VERSION 5.7 ;
  NOWIREEXTENSIONATPIN ON ;
  DIVIDERCHAR "/" ;
  BUSBITCHARS "[]" ;
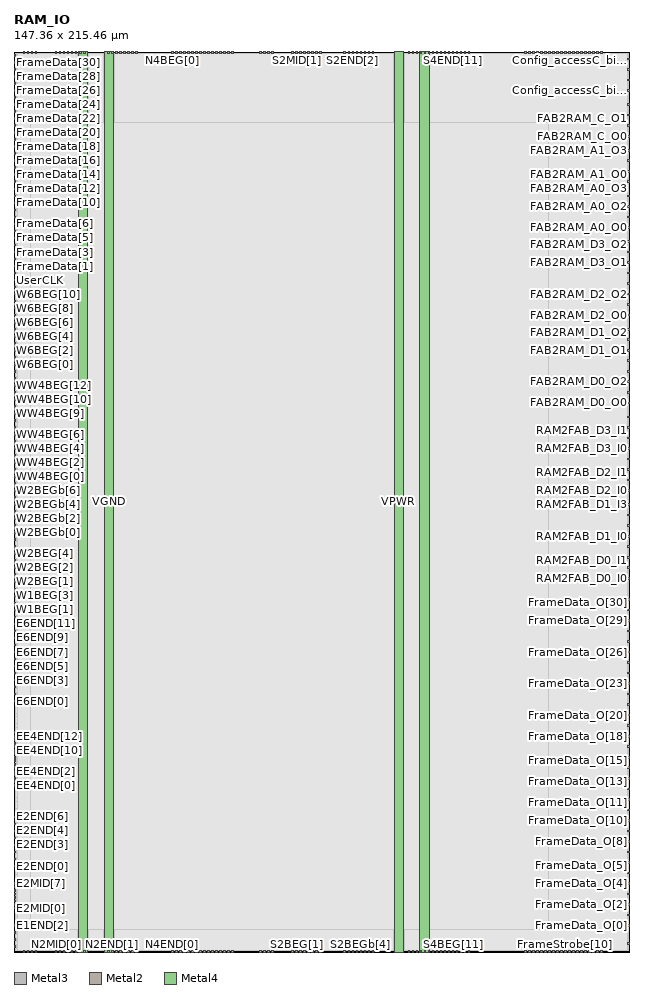
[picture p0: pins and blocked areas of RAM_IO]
MACRO RAM_IO
  CLASS BLOCK ;
  FOREIGN RAM_IO ;
  ORIGIN 0.000 0.000 ;
  SIZE 147.360 BY 215.460 ;
  PIN Config_accessC_bit0
    DIRECTION OUTPUT ;
    USE SIGNAL ;
    ANTENNADIFFAREA 2.647800 ;
    PORT
      LAYER Metal3 ;
        RECT 146.960 206.020 147.360 206.420 ;
    END
  END Config_accessC_bit0
  PIN Config_accessC_bit1
    DIRECTION OUTPUT ;
    USE SIGNAL ;
    ANTENNADIFFAREA 2.647800 ;
    PORT
      LAYER Metal3 ;
        RECT 146.960 208.540 147.360 208.940 ;
    END
  END Config_accessC_bit1
  PIN Config_accessC_bit2
    DIRECTION OUTPUT ;
    USE SIGNAL ;
    ANTENNADIFFAREA 2.647800 ;
    PORT
      LAYER Metal3 ;
        RECT 146.960 211.060 147.360 211.460 ;
    END
  END Config_accessC_bit2
  PIN Config_accessC_bit3
    DIRECTION OUTPUT ;
    USE SIGNAL ;
    ANTENNADIFFAREA 2.647800 ;
    PORT
      LAYER Metal3 ;
        RECT 146.960 213.580 147.360 213.980 ;
    END
  END Config_accessC_bit3
  PIN E1END[0]
    DIRECTION INPUT ;
    USE SIGNAL ;
    ANTENNAGATEAREA 1.521000 ;
    ANTENNADIFFAREA 14.107800 ;
    PORT
      LAYER Metal3 ;
        RECT 0.000 1.060 0.400 1.460 ;
    END
  END E1END[0]
  PIN E1END[1]
    DIRECTION INPUT ;
    USE SIGNAL ;
    ANTENNAGATEAREA 1.534000 ;
    ANTENNADIFFAREA 14.107800 ;
    PORT
      LAYER Metal3 ;
        RECT 0.000 2.740 0.400 3.140 ;
    END
  END E1END[1]
  PIN E1END[2]
    DIRECTION INPUT ;
    USE SIGNAL ;
    ANTENNAGATEAREA 1.521000 ;
    ANTENNADIFFAREA 14.107800 ;
    PORT
      LAYER Metal3 ;
        RECT 0.000 4.420 0.400 4.820 ;
    END
  END E1END[2]
  PIN E1END[3]
    DIRECTION INPUT ;
    USE SIGNAL ;
    ANTENNAGATEAREA 1.534000 ;
    ANTENNADIFFAREA 14.107800 ;
    PORT
      LAYER Metal3 ;
        RECT 0.000 6.100 0.400 6.500 ;
    END
  END E1END[3]
  PIN E2END[0]
    DIRECTION INPUT ;
    USE SIGNAL ;
    ANTENNAGATEAREA 0.668200 ;
    ANTENNADIFFAREA 6.046200 ;
    PORT
      LAYER Metal3 ;
        RECT 0.000 20.380 0.400 20.780 ;
    END
  END E2END[0]
  PIN E2END[1]
    DIRECTION INPUT ;
    USE SIGNAL ;
    ANTENNAGATEAREA 0.668200 ;
    ANTENNADIFFAREA 6.046200 ;
    PORT
      LAYER Metal3 ;
        RECT 0.000 22.060 0.400 22.460 ;
    END
  END E2END[1]
  PIN E2END[2]
    DIRECTION INPUT ;
    USE SIGNAL ;
    ANTENNAGATEAREA 0.668200 ;
    ANTENNADIFFAREA 6.046200 ;
    PORT
      LAYER Metal3 ;
        RECT 0.000 23.740 0.400 24.140 ;
    END
  END E2END[2]
  PIN E2END[3]
    DIRECTION INPUT ;
    USE SIGNAL ;
    ANTENNAGATEAREA 0.668200 ;
    ANTENNADIFFAREA 6.046200 ;
    PORT
      LAYER Metal3 ;
        RECT 0.000 25.420 0.400 25.820 ;
    END
  END E2END[3]
  PIN E2END[4]
    DIRECTION INPUT ;
    USE SIGNAL ;
    ANTENNAGATEAREA 0.668200 ;
    ANTENNADIFFAREA 6.046200 ;
    PORT
      LAYER Metal3 ;
        RECT 0.000 27.100 0.400 27.500 ;
    END
  END E2END[4]
  PIN E2END[5]
    DIRECTION INPUT ;
    USE SIGNAL ;
    ANTENNAGATEAREA 0.668200 ;
    ANTENNADIFFAREA 6.046200 ;
    PORT
      LAYER Metal3 ;
        RECT 0.000 28.780 0.400 29.180 ;
    END
  END E2END[5]
  PIN E2END[6]
    DIRECTION INPUT ;
    USE SIGNAL ;
    ANTENNAGATEAREA 0.668200 ;
    ANTENNADIFFAREA 6.046200 ;
    PORT
      LAYER Metal3 ;
        RECT 0.000 30.460 0.400 30.860 ;
    END
  END E2END[6]
  PIN E2END[7]
    DIRECTION INPUT ;
    USE SIGNAL ;
    ANTENNAGATEAREA 0.668200 ;
    ANTENNADIFFAREA 6.046200 ;
    PORT
      LAYER Metal3 ;
        RECT 0.000 32.140 0.400 32.540 ;
    END
  END E2END[7]
  PIN E2MID[0]
    DIRECTION INPUT ;
    USE SIGNAL ;
    ANTENNAGATEAREA 0.672100 ;
    ANTENNADIFFAREA 6.046200 ;
    PORT
      LAYER Metal3 ;
        RECT 0.000 10.300 0.400 10.700 ;
    END
  END E2MID[0]
  PIN E2MID[1]
    DIRECTION INPUT ;
    USE SIGNAL ;
    ANTENNAGATEAREA 0.672100 ;
    ANTENNADIFFAREA 6.046200 ;
    PORT
      LAYER Metal3 ;
        RECT 0.000 11.140 0.400 11.540 ;
    END
  END E2MID[1]
  PIN E2MID[2]
    DIRECTION INPUT ;
    USE SIGNAL ;
    ANTENNAGATEAREA 0.672100 ;
    ANTENNADIFFAREA 6.046200 ;
    PORT
      LAYER Metal3 ;
        RECT 0.000 11.980 0.400 12.380 ;
    END
  END E2MID[2]
  PIN E2MID[3]
    DIRECTION INPUT ;
    USE SIGNAL ;
    ANTENNAGATEAREA 0.672100 ;
    ANTENNADIFFAREA 6.046200 ;
    PORT
      LAYER Metal3 ;
        RECT 0.000 12.820 0.400 13.220 ;
    END
  END E2MID[3]
  PIN E2MID[4]
    DIRECTION INPUT ;
    USE SIGNAL ;
    ANTENNAGATEAREA 0.672100 ;
    ANTENNADIFFAREA 6.046200 ;
    PORT
      LAYER Metal3 ;
        RECT 0.000 13.660 0.400 14.060 ;
    END
  END E2MID[4]
  PIN E2MID[5]
    DIRECTION INPUT ;
    USE SIGNAL ;
    ANTENNAGATEAREA 0.672100 ;
    ANTENNADIFFAREA 6.046200 ;
    PORT
      LAYER Metal3 ;
        RECT 0.000 14.500 0.400 14.900 ;
    END
  END E2MID[5]
  PIN E2MID[6]
    DIRECTION INPUT ;
    USE SIGNAL ;
    ANTENNAGATEAREA 0.672100 ;
    ANTENNADIFFAREA 6.046200 ;
    PORT
      LAYER Metal3 ;
        RECT 0.000 15.340 0.400 15.740 ;
    END
  END E2MID[6]
  PIN E2MID[7]
    DIRECTION INPUT ;
    USE SIGNAL ;
    ANTENNAGATEAREA 0.672100 ;
    ANTENNADIFFAREA 6.046200 ;
    PORT
      LAYER Metal3 ;
        RECT 0.000 16.180 0.400 16.580 ;
    END
  END E2MID[7]
  PIN E6END[0]
    DIRECTION INPUT ;
    USE SIGNAL ;
    ANTENNAGATEAREA 0.668200 ;
    ANTENNADIFFAREA 6.046200 ;
    PORT
      LAYER Metal3 ;
        RECT 0.000 59.860 0.400 60.260 ;
    END
  END E6END[0]
  PIN E6END[10]
    DIRECTION INPUT ;
    USE SIGNAL ;
    ANTENNAGATEAREA 0.852800 ;
    ANTENNADIFFAREA 8.061600 ;
    PORT
      LAYER Metal3 ;
        RECT 0.000 76.660 0.400 77.060 ;
    END
  END E6END[10]
  PIN E6END[11]
    DIRECTION INPUT ;
    USE SIGNAL ;
    ANTENNAGATEAREA 0.865800 ;
    ANTENNADIFFAREA 8.061600 ;
    PORT
      LAYER Metal3 ;
        RECT 0.000 78.340 0.400 78.740 ;
    END
  END E6END[11]
  PIN E6END[1]
    DIRECTION INPUT ;
    USE SIGNAL ;
    ANTENNAGATEAREA 0.910000 ;
    ANTENNADIFFAREA 8.061600 ;
    PORT
      LAYER Metal3 ;
        RECT 0.000 61.540 0.400 61.940 ;
    END
  END E6END[1]
  PIN E6END[2]
    DIRECTION INPUT ;
    USE SIGNAL ;
    ANTENNAGATEAREA 0.668200 ;
    ANTENNADIFFAREA 6.046200 ;
    PORT
      LAYER Metal3 ;
        RECT 0.000 63.220 0.400 63.620 ;
    END
  END E6END[2]
  PIN E6END[3]
    DIRECTION INPUT ;
    USE SIGNAL ;
    ANTENNAGATEAREA 0.668200 ;
    ANTENNADIFFAREA 6.046200 ;
    PORT
      LAYER Metal3 ;
        RECT 0.000 64.900 0.400 65.300 ;
    END
  END E6END[3]
  PIN E6END[4]
    DIRECTION INPUT ;
    USE SIGNAL ;
    ANTENNAGATEAREA 0.852800 ;
    ANTENNADIFFAREA 8.061600 ;
    PORT
      LAYER Metal3 ;
        RECT 0.000 66.580 0.400 66.980 ;
    END
  END E6END[4]
  PIN E6END[5]
    DIRECTION INPUT ;
    USE SIGNAL ;
    ANTENNAGATEAREA 0.881400 ;
    ANTENNADIFFAREA 8.061600 ;
    PORT
      LAYER Metal3 ;
        RECT 0.000 68.260 0.400 68.660 ;
    END
  END E6END[5]
  PIN E6END[6]
    DIRECTION INPUT ;
    USE SIGNAL ;
    ANTENNAGATEAREA 0.852800 ;
    ANTENNADIFFAREA 8.061600 ;
    PORT
      LAYER Metal3 ;
        RECT 0.000 69.940 0.400 70.340 ;
    END
  END E6END[6]
  PIN E6END[7]
    DIRECTION INPUT ;
    USE SIGNAL ;
    ANTENNAGATEAREA 0.852800 ;
    ANTENNADIFFAREA 8.061600 ;
    PORT
      LAYER Metal3 ;
        RECT 0.000 71.620 0.400 72.020 ;
    END
  END E6END[7]
  PIN E6END[8]
    DIRECTION INPUT ;
    USE SIGNAL ;
    ANTENNAGATEAREA 0.865800 ;
    ANTENNADIFFAREA 8.061600 ;
    PORT
      LAYER Metal3 ;
        RECT 0.000 73.300 0.400 73.700 ;
    END
  END E6END[8]
  PIN E6END[9]
    DIRECTION INPUT ;
    USE SIGNAL ;
    ANTENNAGATEAREA 0.865800 ;
    ANTENNADIFFAREA 8.061600 ;
    PORT
      LAYER Metal3 ;
        RECT 0.000 74.980 0.400 75.380 ;
    END
  END E6END[9]
  PIN EE4END[0]
    DIRECTION INPUT ;
    USE SIGNAL ;
    ANTENNAGATEAREA 0.639600 ;
    ANTENNADIFFAREA 6.046200 ;
    PORT
      LAYER Metal3 ;
        RECT 0.000 39.700 0.400 40.100 ;
    END
  END EE4END[0]
  PIN EE4END[10]
    DIRECTION INPUT ;
    USE SIGNAL ;
    ANTENNAGATEAREA 0.426400 ;
    ANTENNADIFFAREA 4.030800 ;
    PORT
      LAYER Metal3 ;
        RECT 0.000 48.100 0.400 48.500 ;
    END
  END EE4END[10]
  PIN EE4END[11]
    DIRECTION INPUT ;
    USE SIGNAL ;
    ANTENNAGATEAREA 0.426400 ;
    ANTENNADIFFAREA 4.030800 ;
    PORT
      LAYER Metal3 ;
        RECT 0.000 48.940 0.400 49.340 ;
    END
  END EE4END[11]
  PIN EE4END[12]
    DIRECTION INPUT ;
    USE SIGNAL ;
    ANTENNAGATEAREA 0.639600 ;
    ANTENNADIFFAREA 6.046200 ;
    PORT
      LAYER Metal3 ;
        RECT 0.000 49.780 0.400 50.180 ;
    END
  END EE4END[12]
  PIN EE4END[13]
    DIRECTION INPUT ;
    USE SIGNAL ;
    ANTENNAGATEAREA 0.639600 ;
    ANTENNADIFFAREA 6.046200 ;
    PORT
      LAYER Metal3 ;
        RECT 0.000 50.620 0.400 51.020 ;
    END
  END EE4END[13]
  PIN EE4END[14]
    DIRECTION INPUT ;
    USE SIGNAL ;
    ANTENNAGATEAREA 0.639600 ;
    ANTENNADIFFAREA 6.046200 ;
    PORT
      LAYER Metal3 ;
        RECT 0.000 51.460 0.400 51.860 ;
    END
  END EE4END[14]
  PIN EE4END[15]
    DIRECTION INPUT ;
    USE SIGNAL ;
    ANTENNAGATEAREA 0.639600 ;
    ANTENNADIFFAREA 6.046200 ;
    PORT
      LAYER Metal3 ;
        RECT 0.000 52.300 0.400 52.700 ;
    END
  END EE4END[15]
  PIN EE4END[1]
    DIRECTION INPUT ;
    USE SIGNAL ;
    ANTENNAGATEAREA 0.705400 ;
    ANTENNADIFFAREA 6.046200 ;
    PORT
      LAYER Metal3 ;
        RECT 0.000 40.540 0.400 40.940 ;
    END
  END EE4END[1]
  PIN EE4END[2]
    DIRECTION INPUT ;
    USE SIGNAL ;
    ANTENNAGATEAREA 0.639600 ;
    ANTENNADIFFAREA 6.046200 ;
    PORT
      LAYER Metal3 ;
        RECT 0.000 41.380 0.400 41.780 ;
    END
  END EE4END[2]
  PIN EE4END[3]
    DIRECTION INPUT ;
    USE SIGNAL ;
    ANTENNAGATEAREA 0.705400 ;
    ANTENNADIFFAREA 6.046200 ;
    PORT
      LAYER Metal3 ;
        RECT 0.000 42.220 0.400 42.620 ;
    END
  END EE4END[3]
  PIN EE4END[4]
    DIRECTION INPUT ;
    USE SIGNAL ;
    ANTENNAGATEAREA 0.426400 ;
    ANTENNADIFFAREA 4.030800 ;
    PORT
      LAYER Metal3 ;
        RECT 0.000 43.060 0.400 43.460 ;
    END
  END EE4END[4]
  PIN EE4END[5]
    DIRECTION INPUT ;
    USE SIGNAL ;
    ANTENNAGATEAREA 0.426400 ;
    ANTENNADIFFAREA 4.030800 ;
    PORT
      LAYER Metal3 ;
        RECT 0.000 43.900 0.400 44.300 ;
    END
  END EE4END[5]
  PIN EE4END[6]
    DIRECTION INPUT ;
    USE SIGNAL ;
    ANTENNAGATEAREA 0.426400 ;
    ANTENNADIFFAREA 4.030800 ;
    PORT
      LAYER Metal3 ;
        RECT 0.000 44.740 0.400 45.140 ;
    END
  END EE4END[6]
  PIN EE4END[7]
    DIRECTION INPUT ;
    USE SIGNAL ;
    ANTENNAGATEAREA 0.426400 ;
    ANTENNADIFFAREA 4.030800 ;
    PORT
      LAYER Metal3 ;
        RECT 0.000 45.580 0.400 45.980 ;
    END
  END EE4END[7]
  PIN EE4END[8]
    DIRECTION INPUT ;
    USE SIGNAL ;
    ANTENNAGATEAREA 0.426400 ;
    ANTENNADIFFAREA 4.030800 ;
    PORT
      LAYER Metal3 ;
        RECT 0.000 46.420 0.400 46.820 ;
    END
  END EE4END[8]
  PIN EE4END[9]
    DIRECTION INPUT ;
    USE SIGNAL ;
    ANTENNAGATEAREA 0.426400 ;
    ANTENNADIFFAREA 4.030800 ;
    PORT
      LAYER Metal3 ;
        RECT 0.000 47.260 0.400 47.660 ;
    END
  END EE4END[9]
  PIN FAB2RAM_A0_O0
    DIRECTION OUTPUT ;
    USE SIGNAL ;
    ANTENNADIFFAREA 3.023500 ;
    PORT
      LAYER Metal3 ;
        RECT 146.960 173.260 147.360 173.660 ;
    END
  END FAB2RAM_A0_O0
  PIN FAB2RAM_A0_O1
    DIRECTION OUTPUT ;
    USE SIGNAL ;
    ANTENNADIFFAREA 3.023500 ;
    PORT
      LAYER Metal3 ;
        RECT 146.960 175.780 147.360 176.180 ;
    END
  END FAB2RAM_A0_O1
  PIN FAB2RAM_A0_O2
    DIRECTION OUTPUT ;
    USE SIGNAL ;
    ANTENNADIFFAREA 3.023500 ;
    PORT
      LAYER Metal3 ;
        RECT 146.960 178.300 147.360 178.700 ;
    END
  END FAB2RAM_A0_O2
  PIN FAB2RAM_A0_O3
    DIRECTION OUTPUT ;
    USE SIGNAL ;
    ANTENNADIFFAREA 3.023500 ;
    PORT
      LAYER Metal3 ;
        RECT 146.960 180.820 147.360 181.220 ;
    END
  END FAB2RAM_A0_O3
  PIN FAB2RAM_A1_O0
    DIRECTION OUTPUT ;
    USE SIGNAL ;
    ANTENNADIFFAREA 3.023500 ;
    PORT
      LAYER Metal3 ;
        RECT 146.960 184.180 147.360 184.580 ;
    END
  END FAB2RAM_A1_O0
  PIN FAB2RAM_A1_O1
    DIRECTION OUTPUT ;
    USE SIGNAL ;
    ANTENNADIFFAREA 3.023500 ;
    PORT
      LAYER Metal3 ;
        RECT 146.960 186.700 147.360 187.100 ;
    END
  END FAB2RAM_A1_O1
  PIN FAB2RAM_A1_O2
    DIRECTION OUTPUT ;
    USE SIGNAL ;
    ANTENNADIFFAREA 3.023500 ;
    PORT
      LAYER Metal3 ;
        RECT 146.960 189.220 147.360 189.620 ;
    END
  END FAB2RAM_A1_O2
  PIN FAB2RAM_A1_O3
    DIRECTION OUTPUT ;
    USE SIGNAL ;
    ANTENNADIFFAREA 3.023500 ;
    PORT
      LAYER Metal3 ;
        RECT 146.960 191.740 147.360 192.140 ;
    END
  END FAB2RAM_A1_O3
  PIN FAB2RAM_C_O0
    DIRECTION OUTPUT ;
    USE SIGNAL ;
    ANTENNADIFFAREA 2.692600 ;
    PORT
      LAYER Metal3 ;
        RECT 146.960 195.100 147.360 195.500 ;
    END
  END FAB2RAM_C_O0
  PIN FAB2RAM_C_O1
    DIRECTION OUTPUT ;
    USE SIGNAL ;
    ANTENNADIFFAREA 3.023500 ;
    PORT
      LAYER Metal3 ;
        RECT 146.960 197.620 147.360 198.020 ;
    END
  END FAB2RAM_C_O1
  PIN FAB2RAM_C_O2
    DIRECTION OUTPUT ;
    USE SIGNAL ;
    ANTENNADIFFAREA 2.692600 ;
    PORT
      LAYER Metal3 ;
        RECT 146.960 200.140 147.360 200.540 ;
    END
  END FAB2RAM_C_O2
  PIN FAB2RAM_C_O3
    DIRECTION OUTPUT ;
    USE SIGNAL ;
    ANTENNADIFFAREA 2.692600 ;
    PORT
      LAYER Metal3 ;
        RECT 146.960 202.660 147.360 203.060 ;
    END
  END FAB2RAM_C_O3
  PIN FAB2RAM_D0_O0
    DIRECTION OUTPUT ;
    USE SIGNAL ;
    ANTENNADIFFAREA 3.023500 ;
    PORT
      LAYER Metal3 ;
        RECT 146.960 131.260 147.360 131.660 ;
    END
  END FAB2RAM_D0_O0
  PIN FAB2RAM_D0_O1
    DIRECTION OUTPUT ;
    USE SIGNAL ;
    ANTENNADIFFAREA 3.023500 ;
    PORT
      LAYER Metal3 ;
        RECT 146.960 133.780 147.360 134.180 ;
    END
  END FAB2RAM_D0_O1
  PIN FAB2RAM_D0_O2
    DIRECTION OUTPUT ;
    USE SIGNAL ;
    ANTENNADIFFAREA 3.023500 ;
    PORT
      LAYER Metal3 ;
        RECT 146.960 136.300 147.360 136.700 ;
    END
  END FAB2RAM_D0_O2
  PIN FAB2RAM_D0_O3
    DIRECTION OUTPUT ;
    USE SIGNAL ;
    ANTENNADIFFAREA 3.023500 ;
    PORT
      LAYER Metal3 ;
        RECT 146.960 138.820 147.360 139.220 ;
    END
  END FAB2RAM_D0_O3
  PIN FAB2RAM_D1_O0
    DIRECTION OUTPUT ;
    USE SIGNAL ;
    ANTENNADIFFAREA 3.023500 ;
    PORT
      LAYER Metal3 ;
        RECT 146.960 141.340 147.360 141.740 ;
    END
  END FAB2RAM_D1_O0
  PIN FAB2RAM_D1_O1
    DIRECTION OUTPUT ;
    USE SIGNAL ;
    ANTENNADIFFAREA 3.023500 ;
    PORT
      LAYER Metal3 ;
        RECT 146.960 143.860 147.360 144.260 ;
    END
  END FAB2RAM_D1_O1
  PIN FAB2RAM_D1_O2
    DIRECTION OUTPUT ;
    USE SIGNAL ;
    ANTENNADIFFAREA 3.023500 ;
    PORT
      LAYER Metal3 ;
        RECT 146.960 146.380 147.360 146.780 ;
    END
  END FAB2RAM_D1_O2
  PIN FAB2RAM_D1_O3
    DIRECTION OUTPUT ;
    USE SIGNAL ;
    ANTENNADIFFAREA 3.023500 ;
    PORT
      LAYER Metal3 ;
        RECT 146.960 148.900 147.360 149.300 ;
    END
  END FAB2RAM_D1_O3
  PIN FAB2RAM_D2_O0
    DIRECTION OUTPUT ;
    USE SIGNAL ;
    ANTENNADIFFAREA 3.023500 ;
    PORT
      LAYER Metal3 ;
        RECT 146.960 152.260 147.360 152.660 ;
    END
  END FAB2RAM_D2_O0
  PIN FAB2RAM_D2_O1
    DIRECTION OUTPUT ;
    USE SIGNAL ;
    ANTENNADIFFAREA 3.023500 ;
    PORT
      LAYER Metal3 ;
        RECT 146.960 154.780 147.360 155.180 ;
    END
  END FAB2RAM_D2_O1
  PIN FAB2RAM_D2_O2
    DIRECTION OUTPUT ;
    USE SIGNAL ;
    ANTENNADIFFAREA 3.023500 ;
    PORT
      LAYER Metal3 ;
        RECT 146.960 157.300 147.360 157.700 ;
    END
  END FAB2RAM_D2_O2
  PIN FAB2RAM_D2_O3
    DIRECTION OUTPUT ;
    USE SIGNAL ;
    ANTENNADIFFAREA 3.023500 ;
    PORT
      LAYER Metal3 ;
        RECT 146.960 159.820 147.360 160.220 ;
    END
  END FAB2RAM_D2_O3
  PIN FAB2RAM_D3_O0
    DIRECTION OUTPUT ;
    USE SIGNAL ;
    ANTENNADIFFAREA 3.023500 ;
    PORT
      LAYER Metal3 ;
        RECT 146.960 162.340 147.360 162.740 ;
    END
  END FAB2RAM_D3_O0
  PIN FAB2RAM_D3_O1
    DIRECTION OUTPUT ;
    USE SIGNAL ;
    ANTENNADIFFAREA 3.023500 ;
    PORT
      LAYER Metal3 ;
        RECT 146.960 164.860 147.360 165.260 ;
    END
  END FAB2RAM_D3_O1
  PIN FAB2RAM_D3_O2
    DIRECTION OUTPUT ;
    USE SIGNAL ;
    ANTENNADIFFAREA 3.023500 ;
    PORT
      LAYER Metal3 ;
        RECT 146.960 167.380 147.360 167.780 ;
    END
  END FAB2RAM_D3_O2
  PIN FAB2RAM_D3_O3
    DIRECTION OUTPUT ;
    USE SIGNAL ;
    ANTENNADIFFAREA 3.023500 ;
    PORT
      LAYER Metal3 ;
        RECT 146.960 169.900 147.360 170.300 ;
    END
  END FAB2RAM_D3_O3
  PIN FrameData[0]
    DIRECTION INPUT ;
    USE SIGNAL ;
    ANTENNAGATEAREA 1.987700 ;
    ANTENNADIFFAREA 22.169399 ;
    PORT
      LAYER Metal3 ;
        RECT 0.000 162.340 0.400 162.740 ;
    END
  END FrameData[0]
  PIN FrameData[10]
    DIRECTION INPUT ;
    USE SIGNAL ;
    ANTENNAGATEAREA 1.987700 ;
    ANTENNADIFFAREA 22.169399 ;
    PORT
      LAYER Metal3 ;
        RECT 0.000 179.140 0.400 179.540 ;
    END
  END FrameData[10]
  PIN FrameData[11]
    DIRECTION INPUT ;
    USE SIGNAL ;
    ANTENNAGATEAREA 1.987700 ;
    ANTENNADIFFAREA 22.169399 ;
    PORT
      LAYER Metal3 ;
        RECT 0.000 180.820 0.400 181.220 ;
    END
  END FrameData[11]
  PIN FrameData[12]
    DIRECTION INPUT ;
    USE SIGNAL ;
    ANTENNAGATEAREA 1.987700 ;
    ANTENNADIFFAREA 22.169399 ;
    PORT
      LAYER Metal3 ;
        RECT 0.000 182.500 0.400 182.900 ;
    END
  END FrameData[12]
  PIN FrameData[13]
    DIRECTION INPUT ;
    USE SIGNAL ;
    ANTENNAGATEAREA 1.987700 ;
    ANTENNADIFFAREA 22.169399 ;
    PORT
      LAYER Metal3 ;
        RECT 0.000 184.180 0.400 184.580 ;
    END
  END FrameData[13]
  PIN FrameData[14]
    DIRECTION INPUT ;
    USE SIGNAL ;
    ANTENNAGATEAREA 1.987700 ;
    ANTENNADIFFAREA 22.169399 ;
    PORT
      LAYER Metal3 ;
        RECT 0.000 185.860 0.400 186.260 ;
    END
  END FrameData[14]
  PIN FrameData[15]
    DIRECTION INPUT ;
    USE SIGNAL ;
    ANTENNAGATEAREA 1.987700 ;
    ANTENNADIFFAREA 22.169399 ;
    PORT
      LAYER Metal3 ;
        RECT 0.000 187.540 0.400 187.940 ;
    END
  END FrameData[15]
  PIN FrameData[16]
    DIRECTION INPUT ;
    USE SIGNAL ;
    ANTENNAGATEAREA 1.987700 ;
    ANTENNADIFFAREA 22.169399 ;
    PORT
      LAYER Metal3 ;
        RECT 0.000 189.220 0.400 189.620 ;
    END
  END FrameData[16]
  PIN FrameData[17]
    DIRECTION INPUT ;
    USE SIGNAL ;
    ANTENNAGATEAREA 1.987700 ;
    ANTENNADIFFAREA 22.169399 ;
    PORT
      LAYER Metal3 ;
        RECT 0.000 190.900 0.400 191.300 ;
    END
  END FrameData[17]
  PIN FrameData[18]
    DIRECTION INPUT ;
    USE SIGNAL ;
    ANTENNAGATEAREA 1.987700 ;
    ANTENNADIFFAREA 22.169399 ;
    PORT
      LAYER Metal3 ;
        RECT 0.000 192.580 0.400 192.980 ;
    END
  END FrameData[18]
  PIN FrameData[19]
    DIRECTION INPUT ;
    USE SIGNAL ;
    ANTENNAGATEAREA 1.987700 ;
    ANTENNADIFFAREA 22.169399 ;
    PORT
      LAYER Metal3 ;
        RECT 0.000 194.260 0.400 194.660 ;
    END
  END FrameData[19]
  PIN FrameData[1]
    DIRECTION INPUT ;
    USE SIGNAL ;
    ANTENNAGATEAREA 1.987700 ;
    ANTENNADIFFAREA 22.169399 ;
    PORT
      LAYER Metal3 ;
        RECT 0.000 164.020 0.400 164.420 ;
    END
  END FrameData[1]
  PIN FrameData[20]
    DIRECTION INPUT ;
    USE SIGNAL ;
    ANTENNAGATEAREA 1.987700 ;
    ANTENNADIFFAREA 22.169399 ;
    PORT
      LAYER Metal3 ;
        RECT 0.000 195.940 0.400 196.340 ;
    END
  END FrameData[20]
  PIN FrameData[21]
    DIRECTION INPUT ;
    USE SIGNAL ;
    ANTENNAGATEAREA 1.987700 ;
    ANTENNADIFFAREA 22.169399 ;
    PORT
      LAYER Metal3 ;
        RECT 0.000 197.620 0.400 198.020 ;
    END
  END FrameData[21]
  PIN FrameData[22]
    DIRECTION INPUT ;
    USE SIGNAL ;
    ANTENNAGATEAREA 1.987700 ;
    ANTENNADIFFAREA 22.169399 ;
    PORT
      LAYER Metal3 ;
        RECT 0.000 199.300 0.400 199.700 ;
    END
  END FrameData[22]
  PIN FrameData[23]
    DIRECTION INPUT ;
    USE SIGNAL ;
    ANTENNAGATEAREA 1.987700 ;
    ANTENNADIFFAREA 22.169399 ;
    PORT
      LAYER Metal3 ;
        RECT 0.000 200.980 0.400 201.380 ;
    END
  END FrameData[23]
  PIN FrameData[24]
    DIRECTION INPUT ;
    USE SIGNAL ;
    ANTENNAGATEAREA 2.168400 ;
    ANTENNADIFFAREA 24.184799 ;
    PORT
      LAYER Metal3 ;
        RECT 0.000 202.660 0.400 203.060 ;
    END
  END FrameData[24]
  PIN FrameData[25]
    DIRECTION INPUT ;
    USE SIGNAL ;
    ANTENNAGATEAREA 2.168400 ;
    ANTENNADIFFAREA 24.184799 ;
    PORT
      LAYER Metal3 ;
        RECT 0.000 204.340 0.400 204.740 ;
    END
  END FrameData[25]
  PIN FrameData[26]
    DIRECTION INPUT ;
    USE SIGNAL ;
    ANTENNAGATEAREA 2.168400 ;
    ANTENNADIFFAREA 24.184799 ;
    PORT
      LAYER Metal3 ;
        RECT 0.000 206.020 0.400 206.420 ;
    END
  END FrameData[26]
  PIN FrameData[27]
    DIRECTION INPUT ;
    USE SIGNAL ;
    ANTENNAGATEAREA 2.168400 ;
    ANTENNADIFFAREA 24.184799 ;
    PORT
      LAYER Metal3 ;
        RECT 0.000 207.700 0.400 208.100 ;
    END
  END FrameData[27]
  PIN FrameData[28]
    DIRECTION INPUT ;
    USE SIGNAL ;
    ANTENNAGATEAREA 2.168400 ;
    ANTENNADIFFAREA 24.184799 ;
    PORT
      LAYER Metal3 ;
        RECT 0.000 209.380 0.400 209.780 ;
    END
  END FrameData[28]
  PIN FrameData[29]
    DIRECTION INPUT ;
    USE SIGNAL ;
    ANTENNAGATEAREA 2.168400 ;
    ANTENNADIFFAREA 24.184799 ;
    PORT
      LAYER Metal3 ;
        RECT 0.000 211.060 0.400 211.460 ;
    END
  END FrameData[29]
  PIN FrameData[2]
    DIRECTION INPUT ;
    USE SIGNAL ;
    ANTENNAGATEAREA 1.987700 ;
    ANTENNADIFFAREA 22.169399 ;
    PORT
      LAYER Metal3 ;
        RECT 0.000 165.700 0.400 166.100 ;
    END
  END FrameData[2]
  PIN FrameData[30]
    DIRECTION INPUT ;
    USE SIGNAL ;
    ANTENNAGATEAREA 2.168400 ;
    ANTENNADIFFAREA 24.184799 ;
    PORT
      LAYER Metal3 ;
        RECT 0.000 212.740 0.400 213.140 ;
    END
  END FrameData[30]
  PIN FrameData[31]
    DIRECTION INPUT ;
    USE SIGNAL ;
    ANTENNAGATEAREA 2.168400 ;
    ANTENNADIFFAREA 24.184799 ;
    PORT
      LAYER Metal3 ;
        RECT 0.000 214.420 0.400 214.820 ;
    END
  END FrameData[31]
  PIN FrameData[3]
    DIRECTION INPUT ;
    USE SIGNAL ;
    ANTENNAGATEAREA 1.987700 ;
    ANTENNADIFFAREA 22.169399 ;
    PORT
      LAYER Metal3 ;
        RECT 0.000 167.380 0.400 167.780 ;
    END
  END FrameData[3]
  PIN FrameData[4]
    DIRECTION INPUT ;
    USE SIGNAL ;
    ANTENNAGATEAREA 1.987700 ;
    ANTENNADIFFAREA 22.169399 ;
    PORT
      LAYER Metal3 ;
        RECT 0.000 169.060 0.400 169.460 ;
    END
  END FrameData[4]
  PIN FrameData[5]
    DIRECTION INPUT ;
    USE SIGNAL ;
    ANTENNAGATEAREA 1.987700 ;
    ANTENNADIFFAREA 22.169399 ;
    PORT
      LAYER Metal3 ;
        RECT 0.000 170.740 0.400 171.140 ;
    END
  END FrameData[5]
  PIN FrameData[6]
    DIRECTION INPUT ;
    USE SIGNAL ;
    ANTENNAGATEAREA 1.987700 ;
    ANTENNADIFFAREA 22.169399 ;
    PORT
      LAYER Metal3 ;
        RECT 0.000 172.420 0.400 172.820 ;
    END
  END FrameData[6]
  PIN FrameData[7]
    DIRECTION INPUT ;
    USE SIGNAL ;
    ANTENNAGATEAREA 1.987700 ;
    ANTENNADIFFAREA 22.169399 ;
    PORT
      LAYER Metal3 ;
        RECT 0.000 174.100 0.400 174.500 ;
    END
  END FrameData[7]
  PIN FrameData[8]
    DIRECTION INPUT ;
    USE SIGNAL ;
    ANTENNAGATEAREA 1.987700 ;
    ANTENNADIFFAREA 22.169399 ;
    PORT
      LAYER Metal3 ;
        RECT 0.000 175.780 0.400 176.180 ;
    END
  END FrameData[8]
  PIN FrameData[9]
    DIRECTION INPUT ;
    USE SIGNAL ;
    ANTENNAGATEAREA 1.987700 ;
    ANTENNADIFFAREA 22.169399 ;
    PORT
      LAYER Metal3 ;
        RECT 0.000 177.460 0.400 177.860 ;
    END
  END FrameData[9]
  PIN FrameData_O[0]
    DIRECTION OUTPUT ;
    USE SIGNAL ;
    ANTENNADIFFAREA 2.724000 ;
    PORT
      LAYER Metal3 ;
        RECT 146.960 6.100 147.360 6.500 ;
    END
  END FrameData_O[0]
  PIN FrameData_O[10]
    DIRECTION OUTPUT ;
    USE SIGNAL ;
    ANTENNADIFFAREA 2.724000 ;
    PORT
      LAYER Metal3 ;
        RECT 146.960 31.300 147.360 31.700 ;
    END
  END FrameData_O[10]
  PIN FrameData_O[11]
    DIRECTION OUTPUT ;
    USE SIGNAL ;
    ANTENNADIFFAREA 2.724000 ;
    PORT
      LAYER Metal3 ;
        RECT 146.960 33.820 147.360 34.220 ;
    END
  END FrameData_O[11]
  PIN FrameData_O[12]
    DIRECTION OUTPUT ;
    USE SIGNAL ;
    ANTENNADIFFAREA 2.724000 ;
    PORT
      LAYER Metal3 ;
        RECT 146.960 36.340 147.360 36.740 ;
    END
  END FrameData_O[12]
  PIN FrameData_O[13]
    DIRECTION OUTPUT ;
    USE SIGNAL ;
    ANTENNADIFFAREA 2.724000 ;
    PORT
      LAYER Metal3 ;
        RECT 146.960 38.860 147.360 39.260 ;
    END
  END FrameData_O[13]
  PIN FrameData_O[14]
    DIRECTION OUTPUT ;
    USE SIGNAL ;
    ANTENNADIFFAREA 2.724000 ;
    PORT
      LAYER Metal3 ;
        RECT 146.960 41.380 147.360 41.780 ;
    END
  END FrameData_O[14]
  PIN FrameData_O[15]
    DIRECTION OUTPUT ;
    USE SIGNAL ;
    ANTENNADIFFAREA 2.724000 ;
    PORT
      LAYER Metal3 ;
        RECT 146.960 43.900 147.360 44.300 ;
    END
  END FrameData_O[15]
  PIN FrameData_O[16]
    DIRECTION OUTPUT ;
    USE SIGNAL ;
    ANTENNADIFFAREA 2.724000 ;
    PORT
      LAYER Metal3 ;
        RECT 146.960 46.420 147.360 46.820 ;
    END
  END FrameData_O[16]
  PIN FrameData_O[17]
    DIRECTION OUTPUT ;
    USE SIGNAL ;
    ANTENNADIFFAREA 2.724000 ;
    PORT
      LAYER Metal3 ;
        RECT 146.960 48.940 147.360 49.340 ;
    END
  END FrameData_O[17]
  PIN FrameData_O[18]
    DIRECTION OUTPUT ;
    USE SIGNAL ;
    ANTENNADIFFAREA 2.724000 ;
    PORT
      LAYER Metal3 ;
        RECT 146.960 51.460 147.360 51.860 ;
    END
  END FrameData_O[18]
  PIN FrameData_O[19]
    DIRECTION OUTPUT ;
    USE SIGNAL ;
    ANTENNADIFFAREA 2.724000 ;
    PORT
      LAYER Metal3 ;
        RECT 146.960 53.980 147.360 54.380 ;
    END
  END FrameData_O[19]
  PIN FrameData_O[1]
    DIRECTION OUTPUT ;
    USE SIGNAL ;
    ANTENNADIFFAREA 2.724000 ;
    PORT
      LAYER Metal3 ;
        RECT 146.960 8.620 147.360 9.020 ;
    END
  END FrameData_O[1]
  PIN FrameData_O[20]
    DIRECTION OUTPUT ;
    USE SIGNAL ;
    ANTENNADIFFAREA 2.724000 ;
    PORT
      LAYER Metal3 ;
        RECT 146.960 56.500 147.360 56.900 ;
    END
  END FrameData_O[20]
  PIN FrameData_O[21]
    DIRECTION OUTPUT ;
    USE SIGNAL ;
    ANTENNADIFFAREA 2.724000 ;
    PORT
      LAYER Metal3 ;
        RECT 146.960 59.020 147.360 59.420 ;
    END
  END FrameData_O[21]
  PIN FrameData_O[22]
    DIRECTION OUTPUT ;
    USE SIGNAL ;
    ANTENNADIFFAREA 2.724000 ;
    PORT
      LAYER Metal3 ;
        RECT 146.960 61.540 147.360 61.940 ;
    END
  END FrameData_O[22]
  PIN FrameData_O[23]
    DIRECTION OUTPUT ;
    USE SIGNAL ;
    ANTENNADIFFAREA 2.724000 ;
    PORT
      LAYER Metal3 ;
        RECT 146.960 64.060 147.360 64.460 ;
    END
  END FrameData_O[23]
  PIN FrameData_O[24]
    DIRECTION OUTPUT ;
    USE SIGNAL ;
    ANTENNADIFFAREA 2.724000 ;
    PORT
      LAYER Metal3 ;
        RECT 146.960 66.580 147.360 66.980 ;
    END
  END FrameData_O[24]
  PIN FrameData_O[25]
    DIRECTION OUTPUT ;
    USE SIGNAL ;
    ANTENNADIFFAREA 2.724000 ;
    PORT
      LAYER Metal3 ;
        RECT 146.960 69.100 147.360 69.500 ;
    END
  END FrameData_O[25]
  PIN FrameData_O[26]
    DIRECTION OUTPUT ;
    USE SIGNAL ;
    ANTENNADIFFAREA 2.724000 ;
    PORT
      LAYER Metal3 ;
        RECT 146.960 71.620 147.360 72.020 ;
    END
  END FrameData_O[26]
  PIN FrameData_O[27]
    DIRECTION OUTPUT ;
    USE SIGNAL ;
    ANTENNADIFFAREA 2.724000 ;
    PORT
      LAYER Metal3 ;
        RECT 146.960 74.140 147.360 74.540 ;
    END
  END FrameData_O[27]
  PIN FrameData_O[28]
    DIRECTION OUTPUT ;
    USE SIGNAL ;
    ANTENNADIFFAREA 2.724000 ;
    PORT
      LAYER Metal3 ;
        RECT 146.960 76.660 147.360 77.060 ;
    END
  END FrameData_O[28]
  PIN FrameData_O[29]
    DIRECTION OUTPUT ;
    USE SIGNAL ;
    ANTENNADIFFAREA 2.724000 ;
    PORT
      LAYER Metal3 ;
        RECT 146.960 79.180 147.360 79.580 ;
    END
  END FrameData_O[29]
  PIN FrameData_O[2]
    DIRECTION OUTPUT ;
    USE SIGNAL ;
    ANTENNADIFFAREA 2.724000 ;
    PORT
      LAYER Metal3 ;
        RECT 146.960 11.140 147.360 11.540 ;
    END
  END FrameData_O[2]
  PIN FrameData_O[30]
    DIRECTION OUTPUT ;
    USE SIGNAL ;
    ANTENNADIFFAREA 2.724000 ;
    PORT
      LAYER Metal3 ;
        RECT 146.960 81.700 147.360 82.100 ;
    END
  END FrameData_O[30]
  PIN FrameData_O[31]
    DIRECTION OUTPUT ;
    USE SIGNAL ;
    ANTENNADIFFAREA 2.724000 ;
    PORT
      LAYER Metal3 ;
        RECT 146.960 84.220 147.360 84.620 ;
    END
  END FrameData_O[31]
  PIN FrameData_O[3]
    DIRECTION OUTPUT ;
    USE SIGNAL ;
    ANTENNADIFFAREA 2.724000 ;
    PORT
      LAYER Metal3 ;
        RECT 146.960 13.660 147.360 14.060 ;
    END
  END FrameData_O[3]
  PIN FrameData_O[4]
    DIRECTION OUTPUT ;
    USE SIGNAL ;
    ANTENNADIFFAREA 2.724000 ;
    PORT
      LAYER Metal3 ;
        RECT 146.960 16.180 147.360 16.580 ;
    END
  END FrameData_O[4]
  PIN FrameData_O[5]
    DIRECTION OUTPUT ;
    USE SIGNAL ;
    ANTENNADIFFAREA 2.724000 ;
    PORT
      LAYER Metal3 ;
        RECT 146.960 18.700 147.360 19.100 ;
    END
  END FrameData_O[5]
  PIN FrameData_O[6]
    DIRECTION OUTPUT ;
    USE SIGNAL ;
    ANTENNADIFFAREA 2.724000 ;
    PORT
      LAYER Metal3 ;
        RECT 146.960 21.220 147.360 21.620 ;
    END
  END FrameData_O[6]
  PIN FrameData_O[7]
    DIRECTION OUTPUT ;
    USE SIGNAL ;
    ANTENNADIFFAREA 2.724000 ;
    PORT
      LAYER Metal3 ;
        RECT 146.960 23.740 147.360 24.140 ;
    END
  END FrameData_O[7]
  PIN FrameData_O[8]
    DIRECTION OUTPUT ;
    USE SIGNAL ;
    ANTENNADIFFAREA 2.724000 ;
    PORT
      LAYER Metal3 ;
        RECT 146.960 26.260 147.360 26.660 ;
    END
  END FrameData_O[8]
  PIN FrameData_O[9]
    DIRECTION OUTPUT ;
    USE SIGNAL ;
    ANTENNADIFFAREA 2.724000 ;
    PORT
      LAYER Metal3 ;
        RECT 146.960 28.780 147.360 29.180 ;
    END
  END FrameData_O[9]
  PIN FrameStrobe[0]
    DIRECTION INPUT ;
    USE SIGNAL ;
    ANTENNAGATEAREA 6.753500 ;
    ANTENNADIFFAREA 66.508202 ;
    PORT
      LAYER Metal2 ;
        RECT 122.200 0.000 122.600 0.400 ;
    END
  END FrameStrobe[0]
  PIN FrameStrobe[10]
    DIRECTION INPUT ;
    USE SIGNAL ;
    ANTENNAGATEAREA 1.823900 ;
    ANTENNADIFFAREA 18.138599 ;
    PORT
      LAYER Metal2 ;
        RECT 131.800 0.000 132.200 0.400 ;
    END
  END FrameStrobe[10]
  PIN FrameStrobe[11]
    DIRECTION INPUT ;
    USE SIGNAL ;
    ANTENNAGATEAREA 0.180700 ;
    ANTENNADIFFAREA 2.015400 ;
    PORT
      LAYER Metal2 ;
        RECT 132.760 0.000 133.160 0.400 ;
    END
  END FrameStrobe[11]
  PIN FrameStrobe[12]
    DIRECTION INPUT ;
    USE SIGNAL ;
    ANTENNAGATEAREA 0.180700 ;
    ANTENNADIFFAREA 2.015400 ;
    PORT
      LAYER Metal2 ;
        RECT 133.720 0.000 134.120 0.400 ;
    END
  END FrameStrobe[12]
  PIN FrameStrobe[13]
    DIRECTION INPUT ;
    USE SIGNAL ;
    ANTENNAGATEAREA 0.180700 ;
    ANTENNADIFFAREA 2.015400 ;
    PORT
      LAYER Metal2 ;
        RECT 134.680 0.000 135.080 0.400 ;
    END
  END FrameStrobe[13]
  PIN FrameStrobe[14]
    DIRECTION INPUT ;
    USE SIGNAL ;
    ANTENNAGATEAREA 0.180700 ;
    ANTENNADIFFAREA 2.015400 ;
    PORT
      LAYER Metal2 ;
        RECT 135.640 0.000 136.040 0.400 ;
    END
  END FrameStrobe[14]
  PIN FrameStrobe[15]
    DIRECTION INPUT ;
    USE SIGNAL ;
    ANTENNAGATEAREA 0.180700 ;
    ANTENNADIFFAREA 2.015400 ;
    PORT
      LAYER Metal2 ;
        RECT 136.600 0.000 137.000 0.400 ;
    END
  END FrameStrobe[15]
  PIN FrameStrobe[16]
    DIRECTION INPUT ;
    USE SIGNAL ;
    ANTENNAGATEAREA 0.180700 ;
    ANTENNADIFFAREA 2.015400 ;
    PORT
      LAYER Metal2 ;
        RECT 137.560 0.000 137.960 0.400 ;
    END
  END FrameStrobe[16]
  PIN FrameStrobe[17]
    DIRECTION INPUT ;
    USE SIGNAL ;
    ANTENNAGATEAREA 0.180700 ;
    ANTENNADIFFAREA 2.015400 ;
    PORT
      LAYER Metal2 ;
        RECT 138.520 0.000 138.920 0.400 ;
    END
  END FrameStrobe[17]
  PIN FrameStrobe[18]
    DIRECTION INPUT ;
    USE SIGNAL ;
    ANTENNAGATEAREA 0.180700 ;
    ANTENNADIFFAREA 2.015400 ;
    PORT
      LAYER Metal2 ;
        RECT 139.480 0.000 139.880 0.400 ;
    END
  END FrameStrobe[18]
  PIN FrameStrobe[19]
    DIRECTION INPUT ;
    USE SIGNAL ;
    ANTENNAGATEAREA 0.180700 ;
    ANTENNADIFFAREA 2.015400 ;
    PORT
      LAYER Metal2 ;
        RECT 140.440 0.000 140.840 0.400 ;
    END
  END FrameStrobe[19]
  PIN FrameStrobe[1]
    DIRECTION INPUT ;
    USE SIGNAL ;
    ANTENNAGATEAREA 6.753500 ;
    ANTENNADIFFAREA 66.508202 ;
    PORT
      LAYER Metal2 ;
        RECT 123.160 0.000 123.560 0.400 ;
    END
  END FrameStrobe[1]
  PIN FrameStrobe[2]
    DIRECTION INPUT ;
    USE SIGNAL ;
    ANTENNAGATEAREA 6.753500 ;
    ANTENNADIFFAREA 66.508202 ;
    PORT
      LAYER Metal2 ;
        RECT 124.120 0.000 124.520 0.400 ;
    END
  END FrameStrobe[2]
  PIN FrameStrobe[3]
    DIRECTION INPUT ;
    USE SIGNAL ;
    ANTENNAGATEAREA 6.753500 ;
    ANTENNADIFFAREA 66.508202 ;
    PORT
      LAYER Metal2 ;
        RECT 125.080 0.000 125.480 0.400 ;
    END
  END FrameStrobe[3]
  PIN FrameStrobe[4]
    DIRECTION INPUT ;
    USE SIGNAL ;
    ANTENNAGATEAREA 6.753500 ;
    ANTENNADIFFAREA 66.508202 ;
    PORT
      LAYER Metal2 ;
        RECT 126.040 0.000 126.440 0.400 ;
    END
  END FrameStrobe[4]
  PIN FrameStrobe[5]
    DIRECTION INPUT ;
    USE SIGNAL ;
    ANTENNAGATEAREA 6.753500 ;
    ANTENNADIFFAREA 66.508202 ;
    PORT
      LAYER Metal2 ;
        RECT 127.000 0.000 127.400 0.400 ;
    END
  END FrameStrobe[5]
  PIN FrameStrobe[6]
    DIRECTION INPUT ;
    USE SIGNAL ;
    ANTENNAGATEAREA 6.753500 ;
    ANTENNADIFFAREA 66.508202 ;
    PORT
      LAYER Metal2 ;
        RECT 127.960 0.000 128.360 0.400 ;
    END
  END FrameStrobe[6]
  PIN FrameStrobe[7]
    DIRECTION INPUT ;
    USE SIGNAL ;
    ANTENNAGATEAREA 6.753500 ;
    ANTENNADIFFAREA 66.508202 ;
    PORT
      LAYER Metal2 ;
        RECT 128.920 0.000 129.320 0.400 ;
    END
  END FrameStrobe[7]
  PIN FrameStrobe[8]
    DIRECTION INPUT ;
    USE SIGNAL ;
    ANTENNAGATEAREA 6.753500 ;
    ANTENNADIFFAREA 66.508202 ;
    PORT
      LAYER Metal2 ;
        RECT 129.880 0.000 130.280 0.400 ;
    END
  END FrameStrobe[8]
  PIN FrameStrobe[9]
    DIRECTION INPUT ;
    USE SIGNAL ;
    ANTENNAGATEAREA 6.753500 ;
    ANTENNADIFFAREA 66.508202 ;
    PORT
      LAYER Metal2 ;
        RECT 130.840 0.000 131.240 0.400 ;
    END
  END FrameStrobe[9]
  PIN FrameStrobe_O[0]
    DIRECTION OUTPUT ;
    USE SIGNAL ;
    ANTENNADIFFAREA 2.724000 ;
    PORT
      LAYER Metal2 ;
        RECT 122.200 215.060 122.600 215.460 ;
    END
  END FrameStrobe_O[0]
  PIN FrameStrobe_O[10]
    DIRECTION OUTPUT ;
    USE SIGNAL ;
    ANTENNADIFFAREA 2.724000 ;
    PORT
      LAYER Metal2 ;
        RECT 131.800 215.060 132.200 215.460 ;
    END
  END FrameStrobe_O[10]
  PIN FrameStrobe_O[11]
    DIRECTION OUTPUT ;
    USE SIGNAL ;
    ANTENNADIFFAREA 2.724000 ;
    PORT
      LAYER Metal2 ;
        RECT 132.760 215.060 133.160 215.460 ;
    END
  END FrameStrobe_O[11]
  PIN FrameStrobe_O[12]
    DIRECTION OUTPUT ;
    USE SIGNAL ;
    ANTENNADIFFAREA 2.724000 ;
    PORT
      LAYER Metal2 ;
        RECT 133.720 215.060 134.120 215.460 ;
    END
  END FrameStrobe_O[12]
  PIN FrameStrobe_O[13]
    DIRECTION OUTPUT ;
    USE SIGNAL ;
    ANTENNADIFFAREA 2.724000 ;
    PORT
      LAYER Metal2 ;
        RECT 134.680 215.060 135.080 215.460 ;
    END
  END FrameStrobe_O[13]
  PIN FrameStrobe_O[14]
    DIRECTION OUTPUT ;
    USE SIGNAL ;
    ANTENNADIFFAREA 2.724000 ;
    PORT
      LAYER Metal2 ;
        RECT 135.640 215.060 136.040 215.460 ;
    END
  END FrameStrobe_O[14]
  PIN FrameStrobe_O[15]
    DIRECTION OUTPUT ;
    USE SIGNAL ;
    ANTENNADIFFAREA 2.724000 ;
    PORT
      LAYER Metal2 ;
        RECT 136.600 215.060 137.000 215.460 ;
    END
  END FrameStrobe_O[15]
  PIN FrameStrobe_O[16]
    DIRECTION OUTPUT ;
    USE SIGNAL ;
    ANTENNADIFFAREA 2.724000 ;
    PORT
      LAYER Metal2 ;
        RECT 137.560 215.060 137.960 215.460 ;
    END
  END FrameStrobe_O[16]
  PIN FrameStrobe_O[17]
    DIRECTION OUTPUT ;
    USE SIGNAL ;
    ANTENNADIFFAREA 2.724000 ;
    PORT
      LAYER Metal2 ;
        RECT 138.520 215.060 138.920 215.460 ;
    END
  END FrameStrobe_O[17]
  PIN FrameStrobe_O[18]
    DIRECTION OUTPUT ;
    USE SIGNAL ;
    ANTENNADIFFAREA 2.724000 ;
    PORT
      LAYER Metal2 ;
        RECT 139.480 215.060 139.880 215.460 ;
    END
  END FrameStrobe_O[18]
  PIN FrameStrobe_O[19]
    DIRECTION OUTPUT ;
    USE SIGNAL ;
    ANTENNADIFFAREA 2.724000 ;
    PORT
      LAYER Metal2 ;
        RECT 140.440 215.060 140.840 215.460 ;
    END
  END FrameStrobe_O[19]
  PIN FrameStrobe_O[1]
    DIRECTION OUTPUT ;
    USE SIGNAL ;
    ANTENNADIFFAREA 2.724000 ;
    PORT
      LAYER Metal2 ;
        RECT 123.160 215.060 123.560 215.460 ;
    END
  END FrameStrobe_O[1]
  PIN FrameStrobe_O[2]
    DIRECTION OUTPUT ;
    USE SIGNAL ;
    ANTENNADIFFAREA 2.724000 ;
    PORT
      LAYER Metal2 ;
        RECT 124.120 215.060 124.520 215.460 ;
    END
  END FrameStrobe_O[2]
  PIN FrameStrobe_O[3]
    DIRECTION OUTPUT ;
    USE SIGNAL ;
    ANTENNADIFFAREA 2.724000 ;
    PORT
      LAYER Metal2 ;
        RECT 125.080 215.060 125.480 215.460 ;
    END
  END FrameStrobe_O[3]
  PIN FrameStrobe_O[4]
    DIRECTION OUTPUT ;
    USE SIGNAL ;
    ANTENNADIFFAREA 2.724000 ;
    PORT
      LAYER Metal2 ;
        RECT 126.040 215.060 126.440 215.460 ;
    END
  END FrameStrobe_O[4]
  PIN FrameStrobe_O[5]
    DIRECTION OUTPUT ;
    USE SIGNAL ;
    ANTENNADIFFAREA 2.724000 ;
    PORT
      LAYER Metal2 ;
        RECT 127.000 215.060 127.400 215.460 ;
    END
  END FrameStrobe_O[5]
  PIN FrameStrobe_O[6]
    DIRECTION OUTPUT ;
    USE SIGNAL ;
    ANTENNADIFFAREA 2.724000 ;
    PORT
      LAYER Metal2 ;
        RECT 127.960 215.060 128.360 215.460 ;
    END
  END FrameStrobe_O[6]
  PIN FrameStrobe_O[7]
    DIRECTION OUTPUT ;
    USE SIGNAL ;
    ANTENNADIFFAREA 2.724000 ;
    PORT
      LAYER Metal2 ;
        RECT 128.920 215.060 129.320 215.460 ;
    END
  END FrameStrobe_O[7]
  PIN FrameStrobe_O[8]
    DIRECTION OUTPUT ;
    USE SIGNAL ;
    ANTENNADIFFAREA 2.724000 ;
    PORT
      LAYER Metal2 ;
        RECT 129.880 215.060 130.280 215.460 ;
    END
  END FrameStrobe_O[8]
  PIN FrameStrobe_O[9]
    DIRECTION OUTPUT ;
    USE SIGNAL ;
    ANTENNADIFFAREA 2.724000 ;
    PORT
      LAYER Metal2 ;
        RECT 130.840 215.060 131.240 215.460 ;
    END
  END FrameStrobe_O[9]
  PIN N1BEG[0]
    DIRECTION OUTPUT ;
    USE SIGNAL ;
    ANTENNADIFFAREA 2.724000 ;
    PORT
      LAYER Metal2 ;
        RECT 2.200 215.060 2.600 215.460 ;
    END
  END N1BEG[0]
  PIN N1BEG[1]
    DIRECTION OUTPUT ;
    USE SIGNAL ;
    ANTENNADIFFAREA 2.724000 ;
    PORT
      LAYER Metal2 ;
        RECT 3.160 215.060 3.560 215.460 ;
    END
  END N1BEG[1]
  PIN N1BEG[2]
    DIRECTION OUTPUT ;
    USE SIGNAL ;
    ANTENNADIFFAREA 2.724000 ;
    PORT
      LAYER Metal2 ;
        RECT 4.120 215.060 4.520 215.460 ;
    END
  END N1BEG[2]
  PIN N1BEG[3]
    DIRECTION OUTPUT ;
    USE SIGNAL ;
    ANTENNADIFFAREA 2.724000 ;
    PORT
      LAYER Metal2 ;
        RECT 5.080 215.060 5.480 215.460 ;
    END
  END N1BEG[3]
  PIN N1END[0]
    DIRECTION INPUT ;
    USE SIGNAL ;
    ANTENNAGATEAREA 1.311700 ;
    ANTENNADIFFAREA 12.092400 ;
    PORT
      LAYER Metal2 ;
        RECT 2.200 0.000 2.600 0.400 ;
    END
  END N1END[0]
  PIN N1END[1]
    DIRECTION INPUT ;
    USE SIGNAL ;
    ANTENNAGATEAREA 1.311700 ;
    ANTENNADIFFAREA 12.092400 ;
    PORT
      LAYER Metal2 ;
        RECT 3.160 0.000 3.560 0.400 ;
    END
  END N1END[1]
  PIN N1END[2]
    DIRECTION INPUT ;
    USE SIGNAL ;
    ANTENNAGATEAREA 1.311700 ;
    ANTENNADIFFAREA 12.092400 ;
    PORT
      LAYER Metal2 ;
        RECT 4.120 0.000 4.520 0.400 ;
    END
  END N1END[2]
  PIN N1END[3]
    DIRECTION INPUT ;
    USE SIGNAL ;
    ANTENNAGATEAREA 1.311700 ;
    ANTENNADIFFAREA 12.092400 ;
    PORT
      LAYER Metal2 ;
        RECT 5.080 0.000 5.480 0.400 ;
    END
  END N1END[3]
  PIN N2BEG[0]
    DIRECTION OUTPUT ;
    USE SIGNAL ;
    ANTENNADIFFAREA 2.724000 ;
    PORT
      LAYER Metal2 ;
        RECT 9.880 215.060 10.280 215.460 ;
    END
  END N2BEG[0]
  PIN N2BEG[1]
    DIRECTION OUTPUT ;
    USE SIGNAL ;
    ANTENNADIFFAREA 2.724000 ;
    PORT
      LAYER Metal2 ;
        RECT 10.840 215.060 11.240 215.460 ;
    END
  END N2BEG[1]
  PIN N2BEG[2]
    DIRECTION OUTPUT ;
    USE SIGNAL ;
    ANTENNADIFFAREA 2.724000 ;
    PORT
      LAYER Metal2 ;
        RECT 11.800 215.060 12.200 215.460 ;
    END
  END N2BEG[2]
  PIN N2BEG[3]
    DIRECTION OUTPUT ;
    USE SIGNAL ;
    ANTENNADIFFAREA 2.724000 ;
    PORT
      LAYER Metal2 ;
        RECT 12.760 215.060 13.160 215.460 ;
    END
  END N2BEG[3]
  PIN N2BEG[4]
    DIRECTION OUTPUT ;
    USE SIGNAL ;
    ANTENNADIFFAREA 2.724000 ;
    PORT
      LAYER Metal2 ;
        RECT 13.720 215.060 14.120 215.460 ;
    END
  END N2BEG[4]
  PIN N2BEG[5]
    DIRECTION OUTPUT ;
    USE SIGNAL ;
    ANTENNADIFFAREA 2.724000 ;
    PORT
      LAYER Metal2 ;
        RECT 14.680 215.060 15.080 215.460 ;
    END
  END N2BEG[5]
  PIN N2BEG[6]
    DIRECTION OUTPUT ;
    USE SIGNAL ;
    ANTENNADIFFAREA 2.724000 ;
    PORT
      LAYER Metal2 ;
        RECT 15.640 215.060 16.040 215.460 ;
    END
  END N2BEG[6]
  PIN N2BEG[7]
    DIRECTION OUTPUT ;
    USE SIGNAL ;
    ANTENNADIFFAREA 2.724000 ;
    PORT
      LAYER Metal2 ;
        RECT 16.600 215.060 17.000 215.460 ;
    END
  END N2BEG[7]
  PIN N2BEGb[0]
    DIRECTION OUTPUT ;
    USE SIGNAL ;
    ANTENNADIFFAREA 2.724000 ;
    PORT
      LAYER Metal2 ;
        RECT 22.360 215.060 22.760 215.460 ;
    END
  END N2BEGb[0]
  PIN N2BEGb[1]
    DIRECTION OUTPUT ;
    USE SIGNAL ;
    ANTENNADIFFAREA 2.724000 ;
    PORT
      LAYER Metal2 ;
        RECT 23.320 215.060 23.720 215.460 ;
    END
  END N2BEGb[1]
  PIN N2BEGb[2]
    DIRECTION OUTPUT ;
    USE SIGNAL ;
    ANTENNADIFFAREA 2.724000 ;
    PORT
      LAYER Metal2 ;
        RECT 24.280 215.060 24.680 215.460 ;
    END
  END N2BEGb[2]
  PIN N2BEGb[3]
    DIRECTION OUTPUT ;
    USE SIGNAL ;
    ANTENNADIFFAREA 2.724000 ;
    PORT
      LAYER Metal2 ;
        RECT 25.240 215.060 25.640 215.460 ;
    END
  END N2BEGb[3]
  PIN N2BEGb[4]
    DIRECTION OUTPUT ;
    USE SIGNAL ;
    ANTENNADIFFAREA 2.724000 ;
    PORT
      LAYER Metal2 ;
        RECT 26.200 215.060 26.600 215.460 ;
    END
  END N2BEGb[4]
  PIN N2BEGb[5]
    DIRECTION OUTPUT ;
    USE SIGNAL ;
    ANTENNADIFFAREA 2.724000 ;
    PORT
      LAYER Metal2 ;
        RECT 27.160 215.060 27.560 215.460 ;
    END
  END N2BEGb[5]
  PIN N2BEGb[6]
    DIRECTION OUTPUT ;
    USE SIGNAL ;
    ANTENNADIFFAREA 2.724000 ;
    PORT
      LAYER Metal2 ;
        RECT 28.120 215.060 28.520 215.460 ;
    END
  END N2BEGb[6]
  PIN N2BEGb[7]
    DIRECTION OUTPUT ;
    USE SIGNAL ;
    ANTENNADIFFAREA 2.724000 ;
    PORT
      LAYER Metal2 ;
        RECT 29.080 215.060 29.480 215.460 ;
    END
  END N2BEGb[7]
  PIN N2END[0]
    DIRECTION INPUT ;
    USE SIGNAL ;
    ANTENNAGATEAREA 0.213200 ;
    ANTENNADIFFAREA 2.015400 ;
    PORT
      LAYER Metal2 ;
        RECT 22.360 0.000 22.760 0.400 ;
    END
  END N2END[0]
  PIN N2END[1]
    DIRECTION INPUT ;
    USE SIGNAL ;
    ANTENNAGATEAREA 0.213200 ;
    ANTENNADIFFAREA 2.015400 ;
    PORT
      LAYER Metal2 ;
        RECT 23.320 0.000 23.720 0.400 ;
    END
  END N2END[1]
  PIN N2END[2]
    DIRECTION INPUT ;
    USE SIGNAL ;
    ANTENNAGATEAREA 0.213200 ;
    ANTENNADIFFAREA 2.015400 ;
    PORT
      LAYER Metal2 ;
        RECT 24.280 0.000 24.680 0.400 ;
    END
  END N2END[2]
  PIN N2END[3]
    DIRECTION INPUT ;
    USE SIGNAL ;
    ANTENNAGATEAREA 0.213200 ;
    ANTENNADIFFAREA 2.015400 ;
    PORT
      LAYER Metal2 ;
        RECT 25.240 0.000 25.640 0.400 ;
    END
  END N2END[3]
  PIN N2END[4]
    DIRECTION INPUT ;
    USE SIGNAL ;
    ANTENNAGATEAREA 0.213200 ;
    ANTENNADIFFAREA 2.015400 ;
    PORT
      LAYER Metal2 ;
        RECT 26.200 0.000 26.600 0.400 ;
    END
  END N2END[4]
  PIN N2END[5]
    DIRECTION INPUT ;
    USE SIGNAL ;
    ANTENNAGATEAREA 0.213200 ;
    ANTENNADIFFAREA 2.015400 ;
    PORT
      LAYER Metal2 ;
        RECT 27.160 0.000 27.560 0.400 ;
    END
  END N2END[5]
  PIN N2END[6]
    DIRECTION INPUT ;
    USE SIGNAL ;
    ANTENNAGATEAREA 0.213200 ;
    ANTENNADIFFAREA 2.015400 ;
    PORT
      LAYER Metal2 ;
        RECT 28.120 0.000 28.520 0.400 ;
    END
  END N2END[6]
  PIN N2END[7]
    DIRECTION INPUT ;
    USE SIGNAL ;
    ANTENNAGATEAREA 0.213200 ;
    ANTENNADIFFAREA 2.015400 ;
    PORT
      LAYER Metal2 ;
        RECT 29.080 0.000 29.480 0.400 ;
    END
  END N2END[7]
  PIN N2MID[0]
    DIRECTION INPUT ;
    USE SIGNAL ;
    ANTENNAGATEAREA 0.393900 ;
    ANTENNADIFFAREA 4.030800 ;
    PORT
      LAYER Metal2 ;
        RECT 9.880 0.000 10.280 0.400 ;
    END
  END N2MID[0]
  PIN N2MID[1]
    DIRECTION INPUT ;
    USE SIGNAL ;
    ANTENNAGATEAREA 0.393900 ;
    ANTENNADIFFAREA 4.030800 ;
    PORT
      LAYER Metal2 ;
        RECT 10.840 0.000 11.240 0.400 ;
    END
  END N2MID[1]
  PIN N2MID[2]
    DIRECTION INPUT ;
    USE SIGNAL ;
    ANTENNAGATEAREA 0.393900 ;
    ANTENNADIFFAREA 4.030800 ;
    PORT
      LAYER Metal2 ;
        RECT 11.800 0.000 12.200 0.400 ;
    END
  END N2MID[2]
  PIN N2MID[3]
    DIRECTION INPUT ;
    USE SIGNAL ;
    ANTENNAGATEAREA 0.393900 ;
    ANTENNADIFFAREA 4.030800 ;
    PORT
      LAYER Metal2 ;
        RECT 12.760 0.000 13.160 0.400 ;
    END
  END N2MID[3]
  PIN N2MID[4]
    DIRECTION INPUT ;
    USE SIGNAL ;
    ANTENNAGATEAREA 0.393900 ;
    ANTENNADIFFAREA 4.030800 ;
    PORT
      LAYER Metal2 ;
        RECT 13.720 0.000 14.120 0.400 ;
    END
  END N2MID[4]
  PIN N2MID[5]
    DIRECTION INPUT ;
    USE SIGNAL ;
    ANTENNAGATEAREA 0.393900 ;
    ANTENNADIFFAREA 4.030800 ;
    PORT
      LAYER Metal2 ;
        RECT 14.680 0.000 15.080 0.400 ;
    END
  END N2MID[5]
  PIN N2MID[6]
    DIRECTION INPUT ;
    USE SIGNAL ;
    ANTENNAGATEAREA 0.393900 ;
    ANTENNADIFFAREA 4.030800 ;
    PORT
      LAYER Metal2 ;
        RECT 15.640 0.000 16.040 0.400 ;
    END
  END N2MID[6]
  PIN N2MID[7]
    DIRECTION INPUT ;
    USE SIGNAL ;
    ANTENNAGATEAREA 0.393900 ;
    ANTENNADIFFAREA 4.030800 ;
    PORT
      LAYER Metal2 ;
        RECT 16.600 0.000 17.000 0.400 ;
    END
  END N2MID[7]
  PIN N4BEG[0]
    DIRECTION OUTPUT ;
    USE SIGNAL ;
    ANTENNADIFFAREA 2.724000 ;
    PORT
      LAYER Metal2 ;
        RECT 37.720 215.060 38.120 215.460 ;
    END
  END N4BEG[0]
  PIN N4BEG[10]
    DIRECTION OUTPUT ;
    USE SIGNAL ;
    ANTENNADIFFAREA 2.724000 ;
    PORT
      LAYER Metal2 ;
        RECT 47.320 215.060 47.720 215.460 ;
    END
  END N4BEG[10]
  PIN N4BEG[11]
    DIRECTION OUTPUT ;
    USE SIGNAL ;
    ANTENNADIFFAREA 2.724000 ;
    PORT
      LAYER Metal2 ;
        RECT 48.280 215.060 48.680 215.460 ;
    END
  END N4BEG[11]
  PIN N4BEG[12]
    DIRECTION OUTPUT ;
    USE SIGNAL ;
    ANTENNADIFFAREA 2.724000 ;
    PORT
      LAYER Metal2 ;
        RECT 49.240 215.060 49.640 215.460 ;
    END
  END N4BEG[12]
  PIN N4BEG[13]
    DIRECTION OUTPUT ;
    USE SIGNAL ;
    ANTENNADIFFAREA 2.724000 ;
    PORT
      LAYER Metal2 ;
        RECT 50.200 215.060 50.600 215.460 ;
    END
  END N4BEG[13]
  PIN N4BEG[14]
    DIRECTION OUTPUT ;
    USE SIGNAL ;
    ANTENNADIFFAREA 2.724000 ;
    PORT
      LAYER Metal2 ;
        RECT 51.160 215.060 51.560 215.460 ;
    END
  END N4BEG[14]
  PIN N4BEG[15]
    DIRECTION OUTPUT ;
    USE SIGNAL ;
    ANTENNADIFFAREA 2.724000 ;
    PORT
      LAYER Metal2 ;
        RECT 52.120 215.060 52.520 215.460 ;
    END
  END N4BEG[15]
  PIN N4BEG[1]
    DIRECTION OUTPUT ;
    USE SIGNAL ;
    ANTENNADIFFAREA 2.724000 ;
    PORT
      LAYER Metal2 ;
        RECT 38.680 215.060 39.080 215.460 ;
    END
  END N4BEG[1]
  PIN N4BEG[2]
    DIRECTION OUTPUT ;
    USE SIGNAL ;
    ANTENNADIFFAREA 2.724000 ;
    PORT
      LAYER Metal2 ;
        RECT 39.640 215.060 40.040 215.460 ;
    END
  END N4BEG[2]
  PIN N4BEG[3]
    DIRECTION OUTPUT ;
    USE SIGNAL ;
    ANTENNADIFFAREA 2.724000 ;
    PORT
      LAYER Metal2 ;
        RECT 40.600 215.060 41.000 215.460 ;
    END
  END N4BEG[3]
  PIN N4BEG[4]
    DIRECTION OUTPUT ;
    USE SIGNAL ;
    ANTENNADIFFAREA 2.724000 ;
    PORT
      LAYER Metal2 ;
        RECT 41.560 215.060 41.960 215.460 ;
    END
  END N4BEG[4]
  PIN N4BEG[5]
    DIRECTION OUTPUT ;
    USE SIGNAL ;
    ANTENNADIFFAREA 2.724000 ;
    PORT
      LAYER Metal2 ;
        RECT 42.520 215.060 42.920 215.460 ;
    END
  END N4BEG[5]
  PIN N4BEG[6]
    DIRECTION OUTPUT ;
    USE SIGNAL ;
    ANTENNADIFFAREA 2.724000 ;
    PORT
      LAYER Metal2 ;
        RECT 43.480 215.060 43.880 215.460 ;
    END
  END N4BEG[6]
  PIN N4BEG[7]
    DIRECTION OUTPUT ;
    USE SIGNAL ;
    ANTENNADIFFAREA 2.724000 ;
    PORT
      LAYER Metal2 ;
        RECT 44.440 215.060 44.840 215.460 ;
    END
  END N4BEG[7]
  PIN N4BEG[8]
    DIRECTION OUTPUT ;
    USE SIGNAL ;
    ANTENNADIFFAREA 2.724000 ;
    PORT
      LAYER Metal2 ;
        RECT 45.400 215.060 45.800 215.460 ;
    END
  END N4BEG[8]
  PIN N4BEG[9]
    DIRECTION OUTPUT ;
    USE SIGNAL ;
    ANTENNADIFFAREA 2.724000 ;
    PORT
      LAYER Metal2 ;
        RECT 46.360 215.060 46.760 215.460 ;
    END
  END N4BEG[9]
  PIN N4END[0]
    DIRECTION INPUT ;
    USE SIGNAL ;
    ANTENNAGATEAREA 1.066000 ;
    ANTENNADIFFAREA 10.077000 ;
    PORT
      LAYER Metal2 ;
        RECT 37.720 0.000 38.120 0.400 ;
    END
  END N4END[0]
  PIN N4END[10]
    DIRECTION INPUT ;
    USE SIGNAL ;
    ANTENNAGATEAREA 0.180700 ;
    ANTENNADIFFAREA 2.015400 ;
    PORT
      LAYER Metal2 ;
        RECT 47.320 0.000 47.720 0.400 ;
    END
  END N4END[10]
  PIN N4END[11]
    DIRECTION INPUT ;
    USE SIGNAL ;
    ANTENNAGATEAREA 0.180700 ;
    ANTENNADIFFAREA 2.015400 ;
    PORT
      LAYER Metal2 ;
        RECT 48.280 0.000 48.680 0.400 ;
    END
  END N4END[11]
  PIN N4END[12]
    DIRECTION INPUT ;
    USE SIGNAL ;
    ANTENNAGATEAREA 0.180700 ;
    ANTENNADIFFAREA 2.015400 ;
    PORT
      LAYER Metal2 ;
        RECT 49.240 0.000 49.640 0.400 ;
    END
  END N4END[12]
  PIN N4END[13]
    DIRECTION INPUT ;
    USE SIGNAL ;
    ANTENNAGATEAREA 0.180700 ;
    ANTENNADIFFAREA 2.015400 ;
    PORT
      LAYER Metal2 ;
        RECT 50.200 0.000 50.600 0.400 ;
    END
  END N4END[13]
  PIN N4END[14]
    DIRECTION INPUT ;
    USE SIGNAL ;
    ANTENNAGATEAREA 0.180700 ;
    ANTENNADIFFAREA 2.015400 ;
    PORT
      LAYER Metal2 ;
        RECT 51.160 0.000 51.560 0.400 ;
    END
  END N4END[14]
  PIN N4END[15]
    DIRECTION INPUT ;
    USE SIGNAL ;
    ANTENNAGATEAREA 0.180700 ;
    ANTENNADIFFAREA 2.015400 ;
    PORT
      LAYER Metal2 ;
        RECT 52.120 0.000 52.520 0.400 ;
    END
  END N4END[15]
  PIN N4END[1]
    DIRECTION INPUT ;
    USE SIGNAL ;
    ANTENNAGATEAREA 1.066000 ;
    ANTENNADIFFAREA 10.077000 ;
    PORT
      LAYER Metal2 ;
        RECT 38.680 0.000 39.080 0.400 ;
    END
  END N4END[1]
  PIN N4END[2]
    DIRECTION INPUT ;
    USE SIGNAL ;
    ANTENNAGATEAREA 1.066000 ;
    ANTENNADIFFAREA 10.077000 ;
    PORT
      LAYER Metal2 ;
        RECT 39.640 0.000 40.040 0.400 ;
    END
  END N4END[2]
  PIN N4END[3]
    DIRECTION INPUT ;
    USE SIGNAL ;
    ANTENNAGATEAREA 1.066000 ;
    ANTENNADIFFAREA 10.077000 ;
    PORT
      LAYER Metal2 ;
        RECT 40.600 0.000 41.000 0.400 ;
    END
  END N4END[3]
  PIN N4END[4]
    DIRECTION INPUT ;
    USE SIGNAL ;
    ANTENNAGATEAREA 0.180700 ;
    ANTENNADIFFAREA 2.015400 ;
    PORT
      LAYER Metal2 ;
        RECT 41.560 0.000 41.960 0.400 ;
    END
  END N4END[4]
  PIN N4END[5]
    DIRECTION INPUT ;
    USE SIGNAL ;
    ANTENNAGATEAREA 0.180700 ;
    ANTENNADIFFAREA 2.015400 ;
    PORT
      LAYER Metal2 ;
        RECT 42.520 0.000 42.920 0.400 ;
    END
  END N4END[5]
  PIN N4END[6]
    DIRECTION INPUT ;
    USE SIGNAL ;
    ANTENNAGATEAREA 0.180700 ;
    ANTENNADIFFAREA 2.015400 ;
    PORT
      LAYER Metal2 ;
        RECT 43.480 0.000 43.880 0.400 ;
    END
  END N4END[6]
  PIN N4END[7]
    DIRECTION INPUT ;
    USE SIGNAL ;
    ANTENNAGATEAREA 0.180700 ;
    ANTENNADIFFAREA 2.015400 ;
    PORT
      LAYER Metal2 ;
        RECT 44.440 0.000 44.840 0.400 ;
    END
  END N4END[7]
  PIN N4END[8]
    DIRECTION INPUT ;
    USE SIGNAL ;
    ANTENNAGATEAREA 0.180700 ;
    ANTENNADIFFAREA 2.015400 ;
    PORT
      LAYER Metal2 ;
        RECT 45.400 0.000 45.800 0.400 ;
    END
  END N4END[8]
  PIN N4END[9]
    DIRECTION INPUT ;
    USE SIGNAL ;
    ANTENNAGATEAREA 0.180700 ;
    ANTENNADIFFAREA 2.015400 ;
    PORT
      LAYER Metal2 ;
        RECT 46.360 0.000 46.760 0.400 ;
    END
  END N4END[9]
  PIN RAM2FAB_D0_I0
    DIRECTION INPUT ;
    USE SIGNAL ;
    ANTENNAGATEAREA 0.335400 ;
    ANTENNADIFFAREA 4.030800 ;
    PORT
      LAYER Metal3 ;
        RECT 146.960 89.260 147.360 89.660 ;
    END
  END RAM2FAB_D0_I0
  PIN RAM2FAB_D0_I1
    DIRECTION INPUT ;
    USE SIGNAL ;
    ANTENNAGATEAREA 0.335400 ;
    ANTENNADIFFAREA 4.030800 ;
    PORT
      LAYER Metal3 ;
        RECT 146.960 91.780 147.360 92.180 ;
    END
  END RAM2FAB_D0_I1
  PIN RAM2FAB_D0_I2
    DIRECTION INPUT ;
    USE SIGNAL ;
    ANTENNAGATEAREA 0.335400 ;
    ANTENNADIFFAREA 4.030800 ;
    PORT
      LAYER Metal3 ;
        RECT 146.960 94.300 147.360 94.700 ;
    END
  END RAM2FAB_D0_I2
  PIN RAM2FAB_D0_I3
    DIRECTION INPUT ;
    USE SIGNAL ;
    ANTENNAGATEAREA 0.335400 ;
    ANTENNADIFFAREA 4.030800 ;
    PORT
      LAYER Metal3 ;
        RECT 146.960 96.820 147.360 97.220 ;
    END
  END RAM2FAB_D0_I3
  PIN RAM2FAB_D1_I0
    DIRECTION INPUT ;
    USE SIGNAL ;
    ANTENNAGATEAREA 0.335400 ;
    ANTENNADIFFAREA 4.030800 ;
    PORT
      LAYER Metal3 ;
        RECT 146.960 99.340 147.360 99.740 ;
    END
  END RAM2FAB_D1_I0
  PIN RAM2FAB_D1_I1
    DIRECTION INPUT ;
    USE SIGNAL ;
    ANTENNAGATEAREA 0.335400 ;
    ANTENNADIFFAREA 4.030800 ;
    PORT
      LAYER Metal3 ;
        RECT 146.960 101.860 147.360 102.260 ;
    END
  END RAM2FAB_D1_I1
  PIN RAM2FAB_D1_I2
    DIRECTION INPUT ;
    USE SIGNAL ;
    ANTENNAGATEAREA 0.335400 ;
    ANTENNADIFFAREA 4.030800 ;
    PORT
      LAYER Metal3 ;
        RECT 146.960 104.380 147.360 104.780 ;
    END
  END RAM2FAB_D1_I2
  PIN RAM2FAB_D1_I3
    DIRECTION INPUT ;
    USE SIGNAL ;
    ANTENNAGATEAREA 0.335400 ;
    ANTENNADIFFAREA 4.030800 ;
    PORT
      LAYER Metal3 ;
        RECT 146.960 106.900 147.360 107.300 ;
    END
  END RAM2FAB_D1_I3
  PIN RAM2FAB_D2_I0
    DIRECTION INPUT ;
    USE SIGNAL ;
    ANTENNAGATEAREA 0.335400 ;
    ANTENNADIFFAREA 4.030800 ;
    PORT
      LAYER Metal3 ;
        RECT 146.960 110.260 147.360 110.660 ;
    END
  END RAM2FAB_D2_I0
  PIN RAM2FAB_D2_I1
    DIRECTION INPUT ;
    USE SIGNAL ;
    ANTENNAGATEAREA 0.335400 ;
    ANTENNADIFFAREA 4.030800 ;
    PORT
      LAYER Metal3 ;
        RECT 146.960 112.780 147.360 113.180 ;
    END
  END RAM2FAB_D2_I1
  PIN RAM2FAB_D2_I2
    DIRECTION INPUT ;
    USE SIGNAL ;
    ANTENNAGATEAREA 0.335400 ;
    ANTENNADIFFAREA 4.030800 ;
    PORT
      LAYER Metal3 ;
        RECT 146.960 115.300 147.360 115.700 ;
    END
  END RAM2FAB_D2_I2
  PIN RAM2FAB_D2_I3
    DIRECTION INPUT ;
    USE SIGNAL ;
    ANTENNAGATEAREA 0.335400 ;
    ANTENNADIFFAREA 4.030800 ;
    PORT
      LAYER Metal3 ;
        RECT 146.960 117.820 147.360 118.220 ;
    END
  END RAM2FAB_D2_I3
  PIN RAM2FAB_D3_I0
    DIRECTION INPUT ;
    USE SIGNAL ;
    ANTENNAGATEAREA 0.335400 ;
    ANTENNADIFFAREA 4.030800 ;
    PORT
      LAYER Metal3 ;
        RECT 146.960 120.340 147.360 120.740 ;
    END
  END RAM2FAB_D3_I0
  PIN RAM2FAB_D3_I1
    DIRECTION INPUT ;
    USE SIGNAL ;
    ANTENNAGATEAREA 0.335400 ;
    ANTENNADIFFAREA 4.030800 ;
    PORT
      LAYER Metal3 ;
        RECT 146.960 122.860 147.360 123.260 ;
    END
  END RAM2FAB_D3_I1
  PIN RAM2FAB_D3_I2
    DIRECTION INPUT ;
    USE SIGNAL ;
    ANTENNAGATEAREA 0.335400 ;
    ANTENNADIFFAREA 4.030800 ;
    PORT
      LAYER Metal3 ;
        RECT 146.960 125.380 147.360 125.780 ;
    END
  END RAM2FAB_D3_I2
  PIN RAM2FAB_D3_I3
    DIRECTION INPUT ;
    USE SIGNAL ;
    ANTENNAGATEAREA 0.335400 ;
    ANTENNADIFFAREA 4.030800 ;
    PORT
      LAYER Metal3 ;
        RECT 146.960 127.900 147.360 128.300 ;
    END
  END RAM2FAB_D3_I3
  PIN S1BEG[0]
    DIRECTION OUTPUT ;
    USE SIGNAL ;
    ANTENNADIFFAREA 2.724000 ;
    PORT
      LAYER Metal2 ;
        RECT 58.840 0.000 59.240 0.400 ;
    END
  END S1BEG[0]
  PIN S1BEG[1]
    DIRECTION OUTPUT ;
    USE SIGNAL ;
    ANTENNADIFFAREA 2.724000 ;
    PORT
      LAYER Metal2 ;
        RECT 59.800 0.000 60.200 0.400 ;
    END
  END S1BEG[1]
  PIN S1BEG[2]
    DIRECTION OUTPUT ;
    USE SIGNAL ;
    ANTENNADIFFAREA 2.724000 ;
    PORT
      LAYER Metal2 ;
        RECT 60.760 0.000 61.160 0.400 ;
    END
  END S1BEG[2]
  PIN S1BEG[3]
    DIRECTION OUTPUT ;
    USE SIGNAL ;
    ANTENNADIFFAREA 2.724000 ;
    PORT
      LAYER Metal2 ;
        RECT 61.720 0.000 62.120 0.400 ;
    END
  END S1BEG[3]
  PIN S1END[0]
    DIRECTION INPUT ;
    USE SIGNAL ;
    ANTENNAGATEAREA 1.307800 ;
    ANTENNADIFFAREA 12.092400 ;
    PORT
      LAYER Metal2 ;
        RECT 58.840 215.060 59.240 215.460 ;
    END
  END S1END[0]
  PIN S1END[1]
    DIRECTION INPUT ;
    USE SIGNAL ;
    ANTENNAGATEAREA 1.307800 ;
    ANTENNADIFFAREA 12.092400 ;
    PORT
      LAYER Metal2 ;
        RECT 59.800 215.060 60.200 215.460 ;
    END
  END S1END[1]
  PIN S1END[2]
    DIRECTION INPUT ;
    USE SIGNAL ;
    ANTENNAGATEAREA 1.307800 ;
    ANTENNADIFFAREA 12.092400 ;
    PORT
      LAYER Metal2 ;
        RECT 60.760 215.060 61.160 215.460 ;
    END
  END S1END[2]
  PIN S1END[3]
    DIRECTION INPUT ;
    USE SIGNAL ;
    ANTENNAGATEAREA 1.307800 ;
    ANTENNADIFFAREA 12.092400 ;
    PORT
      LAYER Metal2 ;
        RECT 61.720 215.060 62.120 215.460 ;
    END
  END S1END[3]
  PIN S2BEG[0]
    DIRECTION OUTPUT ;
    USE SIGNAL ;
    ANTENNADIFFAREA 2.724000 ;
    PORT
      LAYER Metal2 ;
        RECT 66.520 0.000 66.920 0.400 ;
    END
  END S2BEG[0]
  PIN S2BEG[1]
    DIRECTION OUTPUT ;
    USE SIGNAL ;
    ANTENNADIFFAREA 2.724000 ;
    PORT
      LAYER Metal2 ;
        RECT 67.480 0.000 67.880 0.400 ;
    END
  END S2BEG[1]
  PIN S2BEG[2]
    DIRECTION OUTPUT ;
    USE SIGNAL ;
    ANTENNADIFFAREA 2.724000 ;
    PORT
      LAYER Metal2 ;
        RECT 68.440 0.000 68.840 0.400 ;
    END
  END S2BEG[2]
  PIN S2BEG[3]
    DIRECTION OUTPUT ;
    USE SIGNAL ;
    ANTENNADIFFAREA 2.724000 ;
    PORT
      LAYER Metal2 ;
        RECT 69.400 0.000 69.800 0.400 ;
    END
  END S2BEG[3]
  PIN S2BEG[4]
    DIRECTION OUTPUT ;
    USE SIGNAL ;
    ANTENNADIFFAREA 2.724000 ;
    PORT
      LAYER Metal2 ;
        RECT 70.360 0.000 70.760 0.400 ;
    END
  END S2BEG[4]
  PIN S2BEG[5]
    DIRECTION OUTPUT ;
    USE SIGNAL ;
    ANTENNADIFFAREA 2.724000 ;
    PORT
      LAYER Metal2 ;
        RECT 71.320 0.000 71.720 0.400 ;
    END
  END S2BEG[5]
  PIN S2BEG[6]
    DIRECTION OUTPUT ;
    USE SIGNAL ;
    ANTENNADIFFAREA 2.724000 ;
    PORT
      LAYER Metal2 ;
        RECT 72.280 0.000 72.680 0.400 ;
    END
  END S2BEG[6]
  PIN S2BEG[7]
    DIRECTION OUTPUT ;
    USE SIGNAL ;
    ANTENNADIFFAREA 2.724000 ;
    PORT
      LAYER Metal2 ;
        RECT 73.240 0.000 73.640 0.400 ;
    END
  END S2BEG[7]
  PIN S2BEGb[0]
    DIRECTION OUTPUT ;
    USE SIGNAL ;
    ANTENNADIFFAREA 2.724000 ;
    PORT
      LAYER Metal2 ;
        RECT 79.000 0.000 79.400 0.400 ;
    END
  END S2BEGb[0]
  PIN S2BEGb[1]
    DIRECTION OUTPUT ;
    USE SIGNAL ;
    ANTENNADIFFAREA 2.724000 ;
    PORT
      LAYER Metal2 ;
        RECT 79.960 0.000 80.360 0.400 ;
    END
  END S2BEGb[1]
  PIN S2BEGb[2]
    DIRECTION OUTPUT ;
    USE SIGNAL ;
    ANTENNADIFFAREA 2.724000 ;
    PORT
      LAYER Metal2 ;
        RECT 80.920 0.000 81.320 0.400 ;
    END
  END S2BEGb[2]
  PIN S2BEGb[3]
    DIRECTION OUTPUT ;
    USE SIGNAL ;
    ANTENNADIFFAREA 2.724000 ;
    PORT
      LAYER Metal2 ;
        RECT 81.880 0.000 82.280 0.400 ;
    END
  END S2BEGb[3]
  PIN S2BEGb[4]
    DIRECTION OUTPUT ;
    USE SIGNAL ;
    ANTENNADIFFAREA 2.724000 ;
    PORT
      LAYER Metal2 ;
        RECT 82.840 0.000 83.240 0.400 ;
    END
  END S2BEGb[4]
  PIN S2BEGb[5]
    DIRECTION OUTPUT ;
    USE SIGNAL ;
    ANTENNADIFFAREA 2.724000 ;
    PORT
      LAYER Metal2 ;
        RECT 83.800 0.000 84.200 0.400 ;
    END
  END S2BEGb[5]
  PIN S2BEGb[6]
    DIRECTION OUTPUT ;
    USE SIGNAL ;
    ANTENNADIFFAREA 2.724000 ;
    PORT
      LAYER Metal2 ;
        RECT 84.760 0.000 85.160 0.400 ;
    END
  END S2BEGb[6]
  PIN S2BEGb[7]
    DIRECTION OUTPUT ;
    USE SIGNAL ;
    ANTENNADIFFAREA 2.724000 ;
    PORT
      LAYER Metal2 ;
        RECT 85.720 0.000 86.120 0.400 ;
    END
  END S2BEGb[7]
  PIN S2END[0]
    DIRECTION INPUT ;
    USE SIGNAL ;
    ANTENNAGATEAREA 0.213200 ;
    ANTENNADIFFAREA 2.015400 ;
    PORT
      LAYER Metal2 ;
        RECT 79.000 215.060 79.400 215.460 ;
    END
  END S2END[0]
  PIN S2END[1]
    DIRECTION INPUT ;
    USE SIGNAL ;
    ANTENNAGATEAREA 0.213200 ;
    ANTENNADIFFAREA 2.015400 ;
    PORT
      LAYER Metal2 ;
        RECT 79.960 215.060 80.360 215.460 ;
    END
  END S2END[1]
  PIN S2END[2]
    DIRECTION INPUT ;
    USE SIGNAL ;
    ANTENNAGATEAREA 0.213200 ;
    ANTENNADIFFAREA 2.015400 ;
    PORT
      LAYER Metal2 ;
        RECT 80.920 215.060 81.320 215.460 ;
    END
  END S2END[2]
  PIN S2END[3]
    DIRECTION INPUT ;
    USE SIGNAL ;
    ANTENNAGATEAREA 0.213200 ;
    ANTENNADIFFAREA 2.015400 ;
    PORT
      LAYER Metal2 ;
        RECT 81.880 215.060 82.280 215.460 ;
    END
  END S2END[3]
  PIN S2END[4]
    DIRECTION INPUT ;
    USE SIGNAL ;
    ANTENNAGATEAREA 0.213200 ;
    ANTENNADIFFAREA 2.015400 ;
    PORT
      LAYER Metal2 ;
        RECT 82.840 215.060 83.240 215.460 ;
    END
  END S2END[4]
  PIN S2END[5]
    DIRECTION INPUT ;
    USE SIGNAL ;
    ANTENNAGATEAREA 0.213200 ;
    ANTENNADIFFAREA 2.015400 ;
    PORT
      LAYER Metal2 ;
        RECT 83.800 215.060 84.200 215.460 ;
    END
  END S2END[5]
  PIN S2END[6]
    DIRECTION INPUT ;
    USE SIGNAL ;
    ANTENNAGATEAREA 0.213200 ;
    ANTENNADIFFAREA 2.015400 ;
    PORT
      LAYER Metal2 ;
        RECT 84.760 215.060 85.160 215.460 ;
    END
  END S2END[6]
  PIN S2END[7]
    DIRECTION INPUT ;
    USE SIGNAL ;
    ANTENNAGATEAREA 0.213200 ;
    ANTENNADIFFAREA 2.015400 ;
    PORT
      LAYER Metal2 ;
        RECT 85.720 215.060 86.120 215.460 ;
    END
  END S2END[7]
  PIN S2MID[0]
    DIRECTION INPUT ;
    USE SIGNAL ;
    ANTENNAGATEAREA 0.393900 ;
    ANTENNADIFFAREA 4.030800 ;
    PORT
      LAYER Metal2 ;
        RECT 66.520 215.060 66.920 215.460 ;
    END
  END S2MID[0]
  PIN S2MID[1]
    DIRECTION INPUT ;
    USE SIGNAL ;
    ANTENNAGATEAREA 0.393900 ;
    ANTENNADIFFAREA 4.030800 ;
    PORT
      LAYER Metal2 ;
        RECT 67.480 215.060 67.880 215.460 ;
    END
  END S2MID[1]
  PIN S2MID[2]
    DIRECTION INPUT ;
    USE SIGNAL ;
    ANTENNAGATEAREA 0.393900 ;
    ANTENNADIFFAREA 4.030800 ;
    PORT
      LAYER Metal2 ;
        RECT 68.440 215.060 68.840 215.460 ;
    END
  END S2MID[2]
  PIN S2MID[3]
    DIRECTION INPUT ;
    USE SIGNAL ;
    ANTENNAGATEAREA 0.393900 ;
    ANTENNADIFFAREA 4.030800 ;
    PORT
      LAYER Metal2 ;
        RECT 69.400 215.060 69.800 215.460 ;
    END
  END S2MID[3]
  PIN S2MID[4]
    DIRECTION INPUT ;
    USE SIGNAL ;
    ANTENNAGATEAREA 0.393900 ;
    ANTENNADIFFAREA 4.030800 ;
    PORT
      LAYER Metal2 ;
        RECT 70.360 215.060 70.760 215.460 ;
    END
  END S2MID[4]
  PIN S2MID[5]
    DIRECTION INPUT ;
    USE SIGNAL ;
    ANTENNAGATEAREA 0.393900 ;
    ANTENNADIFFAREA 4.030800 ;
    PORT
      LAYER Metal2 ;
        RECT 71.320 215.060 71.720 215.460 ;
    END
  END S2MID[5]
  PIN S2MID[6]
    DIRECTION INPUT ;
    USE SIGNAL ;
    ANTENNAGATEAREA 0.393900 ;
    ANTENNADIFFAREA 4.030800 ;
    PORT
      LAYER Metal2 ;
        RECT 72.280 215.060 72.680 215.460 ;
    END
  END S2MID[6]
  PIN S2MID[7]
    DIRECTION INPUT ;
    USE SIGNAL ;
    ANTENNAGATEAREA 0.393900 ;
    ANTENNADIFFAREA 4.030800 ;
    PORT
      LAYER Metal2 ;
        RECT 73.240 215.060 73.640 215.460 ;
    END
  END S2MID[7]
  PIN S4BEG[0]
    DIRECTION OUTPUT ;
    USE SIGNAL ;
    ANTENNADIFFAREA 2.724000 ;
    PORT
      LAYER Metal2 ;
        RECT 94.360 0.000 94.760 0.400 ;
    END
  END S4BEG[0]
  PIN S4BEG[10]
    DIRECTION OUTPUT ;
    USE SIGNAL ;
    ANTENNADIFFAREA 2.724000 ;
    PORT
      LAYER Metal2 ;
        RECT 103.960 0.000 104.360 0.400 ;
    END
  END S4BEG[10]
  PIN S4BEG[11]
    DIRECTION OUTPUT ;
    USE SIGNAL ;
    ANTENNADIFFAREA 2.724000 ;
    PORT
      LAYER Metal2 ;
        RECT 104.920 0.000 105.320 0.400 ;
    END
  END S4BEG[11]
  PIN S4BEG[12]
    DIRECTION OUTPUT ;
    USE SIGNAL ;
    ANTENNADIFFAREA 2.724000 ;
    PORT
      LAYER Metal2 ;
        RECT 105.880 0.000 106.280 0.400 ;
    END
  END S4BEG[12]
  PIN S4BEG[13]
    DIRECTION OUTPUT ;
    USE SIGNAL ;
    ANTENNADIFFAREA 2.724000 ;
    PORT
      LAYER Metal2 ;
        RECT 106.840 0.000 107.240 0.400 ;
    END
  END S4BEG[13]
  PIN S4BEG[14]
    DIRECTION OUTPUT ;
    USE SIGNAL ;
    ANTENNADIFFAREA 2.724000 ;
    PORT
      LAYER Metal2 ;
        RECT 107.800 0.000 108.200 0.400 ;
    END
  END S4BEG[14]
  PIN S4BEG[15]
    DIRECTION OUTPUT ;
    USE SIGNAL ;
    ANTENNADIFFAREA 2.724000 ;
    PORT
      LAYER Metal2 ;
        RECT 108.760 0.000 109.160 0.400 ;
    END
  END S4BEG[15]
  PIN S4BEG[1]
    DIRECTION OUTPUT ;
    USE SIGNAL ;
    ANTENNADIFFAREA 2.724000 ;
    PORT
      LAYER Metal2 ;
        RECT 95.320 0.000 95.720 0.400 ;
    END
  END S4BEG[1]
  PIN S4BEG[2]
    DIRECTION OUTPUT ;
    USE SIGNAL ;
    ANTENNADIFFAREA 2.724000 ;
    PORT
      LAYER Metal2 ;
        RECT 96.280 0.000 96.680 0.400 ;
    END
  END S4BEG[2]
  PIN S4BEG[3]
    DIRECTION OUTPUT ;
    USE SIGNAL ;
    ANTENNADIFFAREA 2.724000 ;
    PORT
      LAYER Metal2 ;
        RECT 97.240 0.000 97.640 0.400 ;
    END
  END S4BEG[3]
  PIN S4BEG[4]
    DIRECTION OUTPUT ;
    USE SIGNAL ;
    ANTENNADIFFAREA 2.724000 ;
    PORT
      LAYER Metal2 ;
        RECT 98.200 0.000 98.600 0.400 ;
    END
  END S4BEG[4]
  PIN S4BEG[5]
    DIRECTION OUTPUT ;
    USE SIGNAL ;
    ANTENNADIFFAREA 2.724000 ;
    PORT
      LAYER Metal2 ;
        RECT 99.160 0.000 99.560 0.400 ;
    END
  END S4BEG[5]
  PIN S4BEG[6]
    DIRECTION OUTPUT ;
    USE SIGNAL ;
    ANTENNADIFFAREA 2.724000 ;
    PORT
      LAYER Metal2 ;
        RECT 100.120 0.000 100.520 0.400 ;
    END
  END S4BEG[6]
  PIN S4BEG[7]
    DIRECTION OUTPUT ;
    USE SIGNAL ;
    ANTENNADIFFAREA 2.724000 ;
    PORT
      LAYER Metal2 ;
        RECT 101.080 0.000 101.480 0.400 ;
    END
  END S4BEG[7]
  PIN S4BEG[8]
    DIRECTION OUTPUT ;
    USE SIGNAL ;
    ANTENNADIFFAREA 2.724000 ;
    PORT
      LAYER Metal2 ;
        RECT 102.040 0.000 102.440 0.400 ;
    END
  END S4BEG[8]
  PIN S4BEG[9]
    DIRECTION OUTPUT ;
    USE SIGNAL ;
    ANTENNADIFFAREA 2.724000 ;
    PORT
      LAYER Metal2 ;
        RECT 103.000 0.000 103.400 0.400 ;
    END
  END S4BEG[9]
  PIN S4END[0]
    DIRECTION INPUT ;
    USE SIGNAL ;
    ANTENNAGATEAREA 1.066000 ;
    ANTENNADIFFAREA 10.077000 ;
    PORT
      LAYER Metal2 ;
        RECT 94.360 215.060 94.760 215.460 ;
    END
  END S4END[0]
  PIN S4END[10]
    DIRECTION INPUT ;
    USE SIGNAL ;
    ANTENNAGATEAREA 0.180700 ;
    ANTENNADIFFAREA 2.015400 ;
    PORT
      LAYER Metal2 ;
        RECT 103.960 215.060 104.360 215.460 ;
    END
  END S4END[10]
  PIN S4END[11]
    DIRECTION INPUT ;
    USE SIGNAL ;
    ANTENNAGATEAREA 0.180700 ;
    ANTENNADIFFAREA 2.015400 ;
    PORT
      LAYER Metal2 ;
        RECT 104.920 215.060 105.320 215.460 ;
    END
  END S4END[11]
  PIN S4END[12]
    DIRECTION INPUT ;
    USE SIGNAL ;
    ANTENNAGATEAREA 0.180700 ;
    ANTENNADIFFAREA 2.015400 ;
    PORT
      LAYER Metal2 ;
        RECT 105.880 215.060 106.280 215.460 ;
    END
  END S4END[12]
  PIN S4END[13]
    DIRECTION INPUT ;
    USE SIGNAL ;
    ANTENNAGATEAREA 0.180700 ;
    ANTENNADIFFAREA 2.015400 ;
    PORT
      LAYER Metal2 ;
        RECT 106.840 215.060 107.240 215.460 ;
    END
  END S4END[13]
  PIN S4END[14]
    DIRECTION INPUT ;
    USE SIGNAL ;
    ANTENNAGATEAREA 0.180700 ;
    ANTENNADIFFAREA 2.015400 ;
    PORT
      LAYER Metal2 ;
        RECT 107.800 215.060 108.200 215.460 ;
    END
  END S4END[14]
  PIN S4END[15]
    DIRECTION INPUT ;
    USE SIGNAL ;
    ANTENNAGATEAREA 0.180700 ;
    ANTENNADIFFAREA 2.015400 ;
    PORT
      LAYER Metal2 ;
        RECT 108.760 215.060 109.160 215.460 ;
    END
  END S4END[15]
  PIN S4END[1]
    DIRECTION INPUT ;
    USE SIGNAL ;
    ANTENNAGATEAREA 1.066000 ;
    ANTENNADIFFAREA 10.077000 ;
    PORT
      LAYER Metal2 ;
        RECT 95.320 215.060 95.720 215.460 ;
    END
  END S4END[1]
  PIN S4END[2]
    DIRECTION INPUT ;
    USE SIGNAL ;
    ANTENNAGATEAREA 1.066000 ;
    ANTENNADIFFAREA 10.077000 ;
    PORT
      LAYER Metal2 ;
        RECT 96.280 215.060 96.680 215.460 ;
    END
  END S4END[2]
  PIN S4END[3]
    DIRECTION INPUT ;
    USE SIGNAL ;
    ANTENNAGATEAREA 1.066000 ;
    ANTENNADIFFAREA 10.077000 ;
    PORT
      LAYER Metal2 ;
        RECT 97.240 215.060 97.640 215.460 ;
    END
  END S4END[3]
  PIN S4END[4]
    DIRECTION INPUT ;
    USE SIGNAL ;
    ANTENNAGATEAREA 0.180700 ;
    ANTENNADIFFAREA 2.015400 ;
    PORT
      LAYER Metal2 ;
        RECT 98.200 215.060 98.600 215.460 ;
    END
  END S4END[4]
  PIN S4END[5]
    DIRECTION INPUT ;
    USE SIGNAL ;
    ANTENNAGATEAREA 0.180700 ;
    ANTENNADIFFAREA 2.015400 ;
    PORT
      LAYER Metal2 ;
        RECT 99.160 215.060 99.560 215.460 ;
    END
  END S4END[5]
  PIN S4END[6]
    DIRECTION INPUT ;
    USE SIGNAL ;
    ANTENNAGATEAREA 0.180700 ;
    ANTENNADIFFAREA 2.015400 ;
    PORT
      LAYER Metal2 ;
        RECT 100.120 215.060 100.520 215.460 ;
    END
  END S4END[6]
  PIN S4END[7]
    DIRECTION INPUT ;
    USE SIGNAL ;
    ANTENNAGATEAREA 0.180700 ;
    ANTENNADIFFAREA 2.015400 ;
    PORT
      LAYER Metal2 ;
        RECT 101.080 215.060 101.480 215.460 ;
    END
  END S4END[7]
  PIN S4END[8]
    DIRECTION INPUT ;
    USE SIGNAL ;
    ANTENNAGATEAREA 0.180700 ;
    ANTENNADIFFAREA 2.015400 ;
    PORT
      LAYER Metal2 ;
        RECT 102.040 215.060 102.440 215.460 ;
    END
  END S4END[8]
  PIN S4END[9]
    DIRECTION INPUT ;
    USE SIGNAL ;
    ANTENNAGATEAREA 0.180700 ;
    ANTENNADIFFAREA 2.015400 ;
    PORT
      LAYER Metal2 ;
        RECT 103.000 215.060 103.400 215.460 ;
    END
  END S4END[9]
  PIN UserCLK
    DIRECTION INPUT ;
    USE SIGNAL ;
    ANTENNAGATEAREA 1.450800 ;
    PORT
      LAYER Metal3 ;
        RECT 0.000 160.660 0.400 161.060 ;
    END
  END UserCLK
  PIN UserCLKo
    DIRECTION OUTPUT ;
    USE SIGNAL ;
    ANTENNADIFFAREA 2.724000 ;
    PORT
      LAYER Metal3 ;
        RECT 146.960 1.900 147.360 2.300 ;
    END
  END UserCLKo
  PIN VGND
    DIRECTION INOUT ;
    USE GROUND ;
    PORT
      LAYER Metal4 ;
        RECT 21.580 0.000 23.780 215.460 ;
    END
    PORT
      LAYER Metal4 ;
        RECT 97.180 0.000 99.380 215.460 ;
    END
  END VGND
  PIN VPWR
    DIRECTION INOUT ;
    USE POWER ;
    PORT
      LAYER Metal4 ;
        RECT 15.380 0.000 17.580 215.460 ;
    END
    PORT
      LAYER Metal4 ;
        RECT 90.980 0.000 93.180 215.460 ;
    END
  END VPWR
  PIN W1BEG[0]
    DIRECTION OUTPUT ;
    USE SIGNAL ;
    ANTENNADIFFAREA 2.724000 ;
    PORT
      LAYER Metal3 ;
        RECT 0.000 80.020 0.400 80.420 ;
    END
  END W1BEG[0]
  PIN W1BEG[1]
    DIRECTION OUTPUT ;
    USE SIGNAL ;
    ANTENNADIFFAREA 2.724000 ;
    PORT
      LAYER Metal3 ;
        RECT 0.000 81.700 0.400 82.100 ;
    END
  END W1BEG[1]
  PIN W1BEG[2]
    DIRECTION OUTPUT ;
    USE SIGNAL ;
    ANTENNADIFFAREA 2.724000 ;
    PORT
      LAYER Metal3 ;
        RECT 0.000 83.380 0.400 83.780 ;
    END
  END W1BEG[2]
  PIN W1BEG[3]
    DIRECTION OUTPUT ;
    USE SIGNAL ;
    ANTENNADIFFAREA 2.724000 ;
    PORT
      LAYER Metal3 ;
        RECT 0.000 85.060 0.400 85.460 ;
    END
  END W1BEG[3]
  PIN W2BEG[0]
    DIRECTION OUTPUT ;
    USE SIGNAL ;
    ANTENNADIFFAREA 2.724000 ;
    PORT
      LAYER Metal3 ;
        RECT 0.000 86.740 0.400 87.140 ;
    END
  END W2BEG[0]
  PIN W2BEG[1]
    DIRECTION OUTPUT ;
    USE SIGNAL ;
    ANTENNADIFFAREA 2.724000 ;
    PORT
      LAYER Metal3 ;
        RECT 0.000 88.420 0.400 88.820 ;
    END
  END W2BEG[1]
  PIN W2BEG[2]
    DIRECTION OUTPUT ;
    USE SIGNAL ;
    ANTENNADIFFAREA 2.724000 ;
    PORT
      LAYER Metal3 ;
        RECT 0.000 90.100 0.400 90.500 ;
    END
  END W2BEG[2]
  PIN W2BEG[3]
    DIRECTION OUTPUT ;
    USE SIGNAL ;
    ANTENNADIFFAREA 2.724000 ;
    PORT
      LAYER Metal3 ;
        RECT 0.000 91.780 0.400 92.180 ;
    END
  END W2BEG[3]
  PIN W2BEG[4]
    DIRECTION OUTPUT ;
    USE SIGNAL ;
    ANTENNADIFFAREA 2.724000 ;
    PORT
      LAYER Metal3 ;
        RECT 0.000 93.460 0.400 93.860 ;
    END
  END W2BEG[4]
  PIN W2BEG[5]
    DIRECTION OUTPUT ;
    USE SIGNAL ;
    ANTENNADIFFAREA 2.724000 ;
    PORT
      LAYER Metal3 ;
        RECT 0.000 95.140 0.400 95.540 ;
    END
  END W2BEG[5]
  PIN W2BEG[6]
    DIRECTION OUTPUT ;
    USE SIGNAL ;
    ANTENNADIFFAREA 2.724000 ;
    PORT
      LAYER Metal3 ;
        RECT 0.000 96.820 0.400 97.220 ;
    END
  END W2BEG[6]
  PIN W2BEG[7]
    DIRECTION OUTPUT ;
    USE SIGNAL ;
    ANTENNADIFFAREA 2.724000 ;
    PORT
      LAYER Metal3 ;
        RECT 0.000 98.500 0.400 98.900 ;
    END
  END W2BEG[7]
  PIN W2BEGb[0]
    DIRECTION OUTPUT ;
    USE SIGNAL ;
    ANTENNADIFFAREA 2.724000 ;
    PORT
      LAYER Metal3 ;
        RECT 0.000 100.180 0.400 100.580 ;
    END
  END W2BEGb[0]
  PIN W2BEGb[1]
    DIRECTION OUTPUT ;
    USE SIGNAL ;
    ANTENNADIFFAREA 2.724000 ;
    PORT
      LAYER Metal3 ;
        RECT 0.000 101.860 0.400 102.260 ;
    END
  END W2BEGb[1]
  PIN W2BEGb[2]
    DIRECTION OUTPUT ;
    USE SIGNAL ;
    ANTENNADIFFAREA 2.724000 ;
    PORT
      LAYER Metal3 ;
        RECT 0.000 103.540 0.400 103.940 ;
    END
  END W2BEGb[2]
  PIN W2BEGb[3]
    DIRECTION OUTPUT ;
    USE SIGNAL ;
    ANTENNADIFFAREA 2.724000 ;
    PORT
      LAYER Metal3 ;
        RECT 0.000 105.220 0.400 105.620 ;
    END
  END W2BEGb[3]
  PIN W2BEGb[4]
    DIRECTION OUTPUT ;
    USE SIGNAL ;
    ANTENNADIFFAREA 2.724000 ;
    PORT
      LAYER Metal3 ;
        RECT 0.000 106.900 0.400 107.300 ;
    END
  END W2BEGb[4]
  PIN W2BEGb[5]
    DIRECTION OUTPUT ;
    USE SIGNAL ;
    ANTENNADIFFAREA 2.724000 ;
    PORT
      LAYER Metal3 ;
        RECT 0.000 108.580 0.400 108.980 ;
    END
  END W2BEGb[5]
  PIN W2BEGb[6]
    DIRECTION OUTPUT ;
    USE SIGNAL ;
    ANTENNADIFFAREA 2.724000 ;
    PORT
      LAYER Metal3 ;
        RECT 0.000 110.260 0.400 110.660 ;
    END
  END W2BEGb[6]
  PIN W2BEGb[7]
    DIRECTION OUTPUT ;
    USE SIGNAL ;
    ANTENNADIFFAREA 2.724000 ;
    PORT
      LAYER Metal3 ;
        RECT 0.000 111.940 0.400 112.340 ;
    END
  END W2BEGb[7]
  PIN W6BEG[0]
    DIRECTION OUTPUT ;
    USE SIGNAL ;
    ANTENNADIFFAREA 2.724000 ;
    PORT
      LAYER Metal3 ;
        RECT 0.000 140.500 0.400 140.900 ;
    END
  END W6BEG[0]
  PIN W6BEG[10]
    DIRECTION OUTPUT ;
    USE SIGNAL ;
    ANTENNADIFFAREA 2.724000 ;
    PORT
      LAYER Metal3 ;
        RECT 0.000 157.300 0.400 157.700 ;
    END
  END W6BEG[10]
  PIN W6BEG[11]
    DIRECTION OUTPUT ;
    USE SIGNAL ;
    ANTENNADIFFAREA 2.724000 ;
    PORT
      LAYER Metal3 ;
        RECT 0.000 158.980 0.400 159.380 ;
    END
  END W6BEG[11]
  PIN W6BEG[1]
    DIRECTION OUTPUT ;
    USE SIGNAL ;
    ANTENNADIFFAREA 2.724000 ;
    PORT
      LAYER Metal3 ;
        RECT 0.000 142.180 0.400 142.580 ;
    END
  END W6BEG[1]
  PIN W6BEG[2]
    DIRECTION OUTPUT ;
    USE SIGNAL ;
    ANTENNADIFFAREA 2.724000 ;
    PORT
      LAYER Metal3 ;
        RECT 0.000 143.860 0.400 144.260 ;
    END
  END W6BEG[2]
  PIN W6BEG[3]
    DIRECTION OUTPUT ;
    USE SIGNAL ;
    ANTENNADIFFAREA 2.724000 ;
    PORT
      LAYER Metal3 ;
        RECT 0.000 145.540 0.400 145.940 ;
    END
  END W6BEG[3]
  PIN W6BEG[4]
    DIRECTION OUTPUT ;
    USE SIGNAL ;
    ANTENNADIFFAREA 2.724000 ;
    PORT
      LAYER Metal3 ;
        RECT 0.000 147.220 0.400 147.620 ;
    END
  END W6BEG[4]
  PIN W6BEG[5]
    DIRECTION OUTPUT ;
    USE SIGNAL ;
    ANTENNADIFFAREA 2.724000 ;
    PORT
      LAYER Metal3 ;
        RECT 0.000 148.900 0.400 149.300 ;
    END
  END W6BEG[5]
  PIN W6BEG[6]
    DIRECTION OUTPUT ;
    USE SIGNAL ;
    ANTENNADIFFAREA 2.724000 ;
    PORT
      LAYER Metal3 ;
        RECT 0.000 150.580 0.400 150.980 ;
    END
  END W6BEG[6]
  PIN W6BEG[7]
    DIRECTION OUTPUT ;
    USE SIGNAL ;
    ANTENNADIFFAREA 2.724000 ;
    PORT
      LAYER Metal3 ;
        RECT 0.000 152.260 0.400 152.660 ;
    END
  END W6BEG[7]
  PIN W6BEG[8]
    DIRECTION OUTPUT ;
    USE SIGNAL ;
    ANTENNADIFFAREA 2.724000 ;
    PORT
      LAYER Metal3 ;
        RECT 0.000 153.940 0.400 154.340 ;
    END
  END W6BEG[8]
  PIN W6BEG[9]
    DIRECTION OUTPUT ;
    USE SIGNAL ;
    ANTENNADIFFAREA 2.724000 ;
    PORT
      LAYER Metal3 ;
        RECT 0.000 155.620 0.400 156.020 ;
    END
  END W6BEG[9]
  PIN WW4BEG[0]
    DIRECTION OUTPUT ;
    USE SIGNAL ;
    ANTENNADIFFAREA 2.724000 ;
    PORT
      LAYER Metal3 ;
        RECT 0.000 113.620 0.400 114.020 ;
    END
  END WW4BEG[0]
  PIN WW4BEG[10]
    DIRECTION OUTPUT ;
    USE SIGNAL ;
    ANTENNADIFFAREA 2.724000 ;
    PORT
      LAYER Metal3 ;
        RECT 0.000 130.420 0.400 130.820 ;
    END
  END WW4BEG[10]
  PIN WW4BEG[11]
    DIRECTION OUTPUT ;
    USE SIGNAL ;
    ANTENNADIFFAREA 2.724000 ;
    PORT
      LAYER Metal3 ;
        RECT 0.000 132.100 0.400 132.500 ;
    END
  END WW4BEG[11]
  PIN WW4BEG[12]
    DIRECTION OUTPUT ;
    USE SIGNAL ;
    ANTENNADIFFAREA 2.724000 ;
    PORT
      LAYER Metal3 ;
        RECT 0.000 133.780 0.400 134.180 ;
    END
  END WW4BEG[12]
  PIN WW4BEG[13]
    DIRECTION OUTPUT ;
    USE SIGNAL ;
    ANTENNADIFFAREA 2.724000 ;
    PORT
      LAYER Metal3 ;
        RECT 0.000 135.460 0.400 135.860 ;
    END
  END WW4BEG[13]
  PIN WW4BEG[14]
    DIRECTION OUTPUT ;
    USE SIGNAL ;
    ANTENNADIFFAREA 2.724000 ;
    PORT
      LAYER Metal3 ;
        RECT 0.000 137.140 0.400 137.540 ;
    END
  END WW4BEG[14]
  PIN WW4BEG[15]
    DIRECTION OUTPUT ;
    USE SIGNAL ;
    ANTENNADIFFAREA 2.724000 ;
    PORT
      LAYER Metal3 ;
        RECT 0.000 138.820 0.400 139.220 ;
    END
  END WW4BEG[15]
  PIN WW4BEG[1]
    DIRECTION OUTPUT ;
    USE SIGNAL ;
    ANTENNADIFFAREA 2.724000 ;
    PORT
      LAYER Metal3 ;
        RECT 0.000 115.300 0.400 115.700 ;
    END
  END WW4BEG[1]
  PIN WW4BEG[2]
    DIRECTION OUTPUT ;
    USE SIGNAL ;
    ANTENNADIFFAREA 2.724000 ;
    PORT
      LAYER Metal3 ;
        RECT 0.000 116.980 0.400 117.380 ;
    END
  END WW4BEG[2]
  PIN WW4BEG[3]
    DIRECTION OUTPUT ;
    USE SIGNAL ;
    ANTENNADIFFAREA 2.724000 ;
    PORT
      LAYER Metal3 ;
        RECT 0.000 118.660 0.400 119.060 ;
    END
  END WW4BEG[3]
  PIN WW4BEG[4]
    DIRECTION OUTPUT ;
    USE SIGNAL ;
    ANTENNADIFFAREA 2.724000 ;
    PORT
      LAYER Metal3 ;
        RECT 0.000 120.340 0.400 120.740 ;
    END
  END WW4BEG[4]
  PIN WW4BEG[5]
    DIRECTION OUTPUT ;
    USE SIGNAL ;
    ANTENNADIFFAREA 2.724000 ;
    PORT
      LAYER Metal3 ;
        RECT 0.000 122.020 0.400 122.420 ;
    END
  END WW4BEG[5]
  PIN WW4BEG[6]
    DIRECTION OUTPUT ;
    USE SIGNAL ;
    ANTENNADIFFAREA 2.724000 ;
    PORT
      LAYER Metal3 ;
        RECT 0.000 123.700 0.400 124.100 ;
    END
  END WW4BEG[6]
  PIN WW4BEG[7]
    DIRECTION OUTPUT ;
    USE SIGNAL ;
    ANTENNADIFFAREA 2.724000 ;
    PORT
      LAYER Metal3 ;
        RECT 0.000 125.380 0.400 125.780 ;
    END
  END WW4BEG[7]
  PIN WW4BEG[8]
    DIRECTION OUTPUT ;
    USE SIGNAL ;
    ANTENNADIFFAREA 2.724000 ;
    PORT
      LAYER Metal3 ;
        RECT 0.000 127.060 0.400 127.460 ;
    END
  END WW4BEG[8]
  PIN WW4BEG[9]
    DIRECTION OUTPUT ;
    USE SIGNAL ;
    ANTENNADIFFAREA 2.724000 ;
    PORT
      LAYER Metal3 ;
        RECT 0.000 128.740 0.400 129.140 ;
    END
  END WW4BEG[9]
  OBS
      LAYER GatPoly ;
        RECT 2.880 3.630 144.480 211.830 ;
      LAYER Metal1 ;
        RECT 2.880 3.560 144.480 211.900 ;
      LAYER Metal2 ;
        RECT 0.375 214.850 1.990 215.185 ;
        RECT 2.810 214.850 2.950 215.185 ;
        RECT 3.770 214.850 3.910 215.185 ;
        RECT 4.730 214.850 4.870 215.185 ;
        RECT 5.690 214.850 9.670 215.185 ;
        RECT 10.490 214.850 10.630 215.185 ;
        RECT 11.450 214.850 11.590 215.185 ;
        RECT 12.410 214.850 12.550 215.185 ;
        RECT 13.370 214.850 13.510 215.185 ;
        RECT 14.330 214.850 14.470 215.185 ;
        RECT 15.290 214.850 15.430 215.185 ;
        RECT 16.250 214.850 16.390 215.185 ;
        RECT 17.210 214.850 22.150 215.185 ;
        RECT 22.970 214.850 23.110 215.185 ;
        RECT 23.930 214.850 24.070 215.185 ;
        RECT 24.890 214.850 25.030 215.185 ;
        RECT 25.850 214.850 25.990 215.185 ;
        RECT 26.810 214.850 26.950 215.185 ;
        RECT 27.770 214.850 27.910 215.185 ;
        RECT 28.730 214.850 28.870 215.185 ;
        RECT 29.690 214.850 37.510 215.185 ;
        RECT 38.330 214.850 38.470 215.185 ;
        RECT 39.290 214.850 39.430 215.185 ;
        RECT 40.250 214.850 40.390 215.185 ;
        RECT 41.210 214.850 41.350 215.185 ;
        RECT 42.170 214.850 42.310 215.185 ;
        RECT 43.130 214.850 43.270 215.185 ;
        RECT 44.090 214.850 44.230 215.185 ;
        RECT 45.050 214.850 45.190 215.185 ;
        RECT 46.010 214.850 46.150 215.185 ;
        RECT 46.970 214.850 47.110 215.185 ;
        RECT 47.930 214.850 48.070 215.185 ;
        RECT 48.890 214.850 49.030 215.185 ;
        RECT 49.850 214.850 49.990 215.185 ;
        RECT 50.810 214.850 50.950 215.185 ;
        RECT 51.770 214.850 51.910 215.185 ;
        RECT 52.730 214.850 58.630 215.185 ;
        RECT 59.450 214.850 59.590 215.185 ;
        RECT 60.410 214.850 60.550 215.185 ;
        RECT 61.370 214.850 61.510 215.185 ;
        RECT 62.330 214.850 66.310 215.185 ;
        RECT 67.130 214.850 67.270 215.185 ;
        RECT 68.090 214.850 68.230 215.185 ;
        RECT 69.050 214.850 69.190 215.185 ;
        RECT 70.010 214.850 70.150 215.185 ;
        RECT 70.970 214.850 71.110 215.185 ;
        RECT 71.930 214.850 72.070 215.185 ;
        RECT 72.890 214.850 73.030 215.185 ;
        RECT 73.850 214.850 78.790 215.185 ;
        RECT 79.610 214.850 79.750 215.185 ;
        RECT 80.570 214.850 80.710 215.185 ;
        RECT 81.530 214.850 81.670 215.185 ;
        RECT 82.490 214.850 82.630 215.185 ;
        RECT 83.450 214.850 83.590 215.185 ;
        RECT 84.410 214.850 84.550 215.185 ;
        RECT 85.370 214.850 85.510 215.185 ;
        RECT 86.330 214.850 94.150 215.185 ;
        RECT 94.970 214.850 95.110 215.185 ;
        RECT 95.930 214.850 96.070 215.185 ;
        RECT 96.890 214.850 97.030 215.185 ;
        RECT 97.850 214.850 97.990 215.185 ;
        RECT 98.810 214.850 98.950 215.185 ;
        RECT 99.770 214.850 99.910 215.185 ;
        RECT 100.730 214.850 100.870 215.185 ;
        RECT 101.690 214.850 101.830 215.185 ;
        RECT 102.650 214.850 102.790 215.185 ;
        RECT 103.610 214.850 103.750 215.185 ;
        RECT 104.570 214.850 104.710 215.185 ;
        RECT 105.530 214.850 105.670 215.185 ;
        RECT 106.490 214.850 106.630 215.185 ;
        RECT 107.450 214.850 107.590 215.185 ;
        RECT 108.410 214.850 108.550 215.185 ;
        RECT 109.370 214.850 121.990 215.185 ;
        RECT 122.810 214.850 122.950 215.185 ;
        RECT 123.770 214.850 123.910 215.185 ;
        RECT 124.730 214.850 124.870 215.185 ;
        RECT 125.690 214.850 125.830 215.185 ;
        RECT 126.650 214.850 126.790 215.185 ;
        RECT 127.610 214.850 127.750 215.185 ;
        RECT 128.570 214.850 128.710 215.185 ;
        RECT 129.530 214.850 129.670 215.185 ;
        RECT 130.490 214.850 130.630 215.185 ;
        RECT 131.450 214.850 131.590 215.185 ;
        RECT 132.410 214.850 132.550 215.185 ;
        RECT 133.370 214.850 133.510 215.185 ;
        RECT 134.330 214.850 134.470 215.185 ;
        RECT 135.290 214.850 135.430 215.185 ;
        RECT 136.250 214.850 136.390 215.185 ;
        RECT 137.210 214.850 137.350 215.185 ;
        RECT 138.170 214.850 138.310 215.185 ;
        RECT 139.130 214.850 139.270 215.185 ;
        RECT 140.090 214.850 140.230 215.185 ;
        RECT 141.050 214.850 146.985 215.185 ;
        RECT 0.375 0.610 146.985 214.850 ;
        RECT 0.375 0.275 1.990 0.610 ;
        RECT 2.810 0.275 2.950 0.610 ;
        RECT 3.770 0.275 3.910 0.610 ;
        RECT 4.730 0.275 4.870 0.610 ;
        RECT 5.690 0.275 9.670 0.610 ;
        RECT 10.490 0.275 10.630 0.610 ;
        RECT 11.450 0.275 11.590 0.610 ;
        RECT 12.410 0.275 12.550 0.610 ;
        RECT 13.370 0.275 13.510 0.610 ;
        RECT 14.330 0.275 14.470 0.610 ;
        RECT 15.290 0.275 15.430 0.610 ;
        RECT 16.250 0.275 16.390 0.610 ;
        RECT 17.210 0.275 22.150 0.610 ;
        RECT 22.970 0.275 23.110 0.610 ;
        RECT 23.930 0.275 24.070 0.610 ;
        RECT 24.890 0.275 25.030 0.610 ;
        RECT 25.850 0.275 25.990 0.610 ;
        RECT 26.810 0.275 26.950 0.610 ;
        RECT 27.770 0.275 27.910 0.610 ;
        RECT 28.730 0.275 28.870 0.610 ;
        RECT 29.690 0.275 37.510 0.610 ;
        RECT 38.330 0.275 38.470 0.610 ;
        RECT 39.290 0.275 39.430 0.610 ;
        RECT 40.250 0.275 40.390 0.610 ;
        RECT 41.210 0.275 41.350 0.610 ;
        RECT 42.170 0.275 42.310 0.610 ;
        RECT 43.130 0.275 43.270 0.610 ;
        RECT 44.090 0.275 44.230 0.610 ;
        RECT 45.050 0.275 45.190 0.610 ;
        RECT 46.010 0.275 46.150 0.610 ;
        RECT 46.970 0.275 47.110 0.610 ;
        RECT 47.930 0.275 48.070 0.610 ;
        RECT 48.890 0.275 49.030 0.610 ;
        RECT 49.850 0.275 49.990 0.610 ;
        RECT 50.810 0.275 50.950 0.610 ;
        RECT 51.770 0.275 51.910 0.610 ;
        RECT 52.730 0.275 58.630 0.610 ;
        RECT 59.450 0.275 59.590 0.610 ;
        RECT 60.410 0.275 60.550 0.610 ;
        RECT 61.370 0.275 61.510 0.610 ;
        RECT 62.330 0.275 66.310 0.610 ;
        RECT 67.130 0.275 67.270 0.610 ;
        RECT 68.090 0.275 68.230 0.610 ;
        RECT 69.050 0.275 69.190 0.610 ;
        RECT 70.010 0.275 70.150 0.610 ;
        RECT 70.970 0.275 71.110 0.610 ;
        RECT 71.930 0.275 72.070 0.610 ;
        RECT 72.890 0.275 73.030 0.610 ;
        RECT 73.850 0.275 78.790 0.610 ;
        RECT 79.610 0.275 79.750 0.610 ;
        RECT 80.570 0.275 80.710 0.610 ;
        RECT 81.530 0.275 81.670 0.610 ;
        RECT 82.490 0.275 82.630 0.610 ;
        RECT 83.450 0.275 83.590 0.610 ;
        RECT 84.410 0.275 84.550 0.610 ;
        RECT 85.370 0.275 85.510 0.610 ;
        RECT 86.330 0.275 94.150 0.610 ;
        RECT 94.970 0.275 95.110 0.610 ;
        RECT 95.930 0.275 96.070 0.610 ;
        RECT 96.890 0.275 97.030 0.610 ;
        RECT 97.850 0.275 97.990 0.610 ;
        RECT 98.810 0.275 98.950 0.610 ;
        RECT 99.770 0.275 99.910 0.610 ;
        RECT 100.730 0.275 100.870 0.610 ;
        RECT 101.690 0.275 101.830 0.610 ;
        RECT 102.650 0.275 102.790 0.610 ;
        RECT 103.610 0.275 103.750 0.610 ;
        RECT 104.570 0.275 104.710 0.610 ;
        RECT 105.530 0.275 105.670 0.610 ;
        RECT 106.490 0.275 106.630 0.610 ;
        RECT 107.450 0.275 107.590 0.610 ;
        RECT 108.410 0.275 108.550 0.610 ;
        RECT 109.370 0.275 121.990 0.610 ;
        RECT 122.810 0.275 122.950 0.610 ;
        RECT 123.770 0.275 123.910 0.610 ;
        RECT 124.730 0.275 124.870 0.610 ;
        RECT 125.690 0.275 125.830 0.610 ;
        RECT 126.650 0.275 126.790 0.610 ;
        RECT 127.610 0.275 127.750 0.610 ;
        RECT 128.570 0.275 128.710 0.610 ;
        RECT 129.530 0.275 129.670 0.610 ;
        RECT 130.490 0.275 130.630 0.610 ;
        RECT 131.450 0.275 131.590 0.610 ;
        RECT 132.410 0.275 132.550 0.610 ;
        RECT 133.370 0.275 133.510 0.610 ;
        RECT 134.330 0.275 134.470 0.610 ;
        RECT 135.290 0.275 135.430 0.610 ;
        RECT 136.250 0.275 136.390 0.610 ;
        RECT 137.210 0.275 137.350 0.610 ;
        RECT 138.170 0.275 138.310 0.610 ;
        RECT 139.130 0.275 139.270 0.610 ;
        RECT 140.090 0.275 140.230 0.610 ;
        RECT 141.050 0.275 146.985 0.610 ;
      LAYER Metal3 ;
        RECT 0.335 215.030 147.025 215.145 ;
        RECT 0.610 214.210 147.025 215.030 ;
        RECT 0.335 214.190 147.025 214.210 ;
        RECT 0.335 213.370 146.750 214.190 ;
        RECT 0.335 213.350 147.025 213.370 ;
        RECT 0.610 212.530 147.025 213.350 ;
        RECT 0.335 211.670 147.025 212.530 ;
        RECT 0.610 210.850 146.750 211.670 ;
        RECT 0.335 209.990 147.025 210.850 ;
        RECT 0.610 209.170 147.025 209.990 ;
        RECT 0.335 209.150 147.025 209.170 ;
        RECT 0.335 208.330 146.750 209.150 ;
        RECT 0.335 208.310 147.025 208.330 ;
        RECT 0.610 207.490 147.025 208.310 ;
        RECT 0.335 206.630 147.025 207.490 ;
        RECT 0.610 205.810 146.750 206.630 ;
        RECT 0.335 204.950 147.025 205.810 ;
        RECT 0.610 204.130 147.025 204.950 ;
        RECT 0.335 203.270 147.025 204.130 ;
        RECT 0.610 202.450 146.750 203.270 ;
        RECT 0.335 201.590 147.025 202.450 ;
        RECT 0.610 200.770 147.025 201.590 ;
        RECT 0.335 200.750 147.025 200.770 ;
        RECT 0.335 199.930 146.750 200.750 ;
        RECT 0.335 199.910 147.025 199.930 ;
        RECT 0.610 199.090 147.025 199.910 ;
        RECT 0.335 198.230 147.025 199.090 ;
        RECT 0.610 197.410 146.750 198.230 ;
        RECT 0.335 196.550 147.025 197.410 ;
        RECT 0.610 195.730 147.025 196.550 ;
        RECT 0.335 195.710 147.025 195.730 ;
        RECT 0.335 194.890 146.750 195.710 ;
        RECT 0.335 194.870 147.025 194.890 ;
        RECT 0.610 194.050 147.025 194.870 ;
        RECT 0.335 193.190 147.025 194.050 ;
        RECT 0.610 192.370 147.025 193.190 ;
        RECT 0.335 192.350 147.025 192.370 ;
        RECT 0.335 191.530 146.750 192.350 ;
        RECT 0.335 191.510 147.025 191.530 ;
        RECT 0.610 190.690 147.025 191.510 ;
        RECT 0.335 189.830 147.025 190.690 ;
        RECT 0.610 189.010 146.750 189.830 ;
        RECT 0.335 188.150 147.025 189.010 ;
        RECT 0.610 187.330 147.025 188.150 ;
        RECT 0.335 187.310 147.025 187.330 ;
        RECT 0.335 186.490 146.750 187.310 ;
        RECT 0.335 186.470 147.025 186.490 ;
        RECT 0.610 185.650 147.025 186.470 ;
        RECT 0.335 184.790 147.025 185.650 ;
        RECT 0.610 183.970 146.750 184.790 ;
        RECT 0.335 183.110 147.025 183.970 ;
        RECT 0.610 182.290 147.025 183.110 ;
        RECT 0.335 181.430 147.025 182.290 ;
        RECT 0.610 180.610 146.750 181.430 ;
        RECT 0.335 179.750 147.025 180.610 ;
        RECT 0.610 178.930 147.025 179.750 ;
        RECT 0.335 178.910 147.025 178.930 ;
        RECT 0.335 178.090 146.750 178.910 ;
        RECT 0.335 178.070 147.025 178.090 ;
        RECT 0.610 177.250 147.025 178.070 ;
        RECT 0.335 176.390 147.025 177.250 ;
        RECT 0.610 175.570 146.750 176.390 ;
        RECT 0.335 174.710 147.025 175.570 ;
        RECT 0.610 173.890 147.025 174.710 ;
        RECT 0.335 173.870 147.025 173.890 ;
        RECT 0.335 173.050 146.750 173.870 ;
        RECT 0.335 173.030 147.025 173.050 ;
        RECT 0.610 172.210 147.025 173.030 ;
        RECT 0.335 171.350 147.025 172.210 ;
        RECT 0.610 170.530 147.025 171.350 ;
        RECT 0.335 170.510 147.025 170.530 ;
        RECT 0.335 169.690 146.750 170.510 ;
        RECT 0.335 169.670 147.025 169.690 ;
        RECT 0.610 168.850 147.025 169.670 ;
        RECT 0.335 167.990 147.025 168.850 ;
        RECT 0.610 167.170 146.750 167.990 ;
        RECT 0.335 166.310 147.025 167.170 ;
        RECT 0.610 165.490 147.025 166.310 ;
        RECT 0.335 165.470 147.025 165.490 ;
        RECT 0.335 164.650 146.750 165.470 ;
        RECT 0.335 164.630 147.025 164.650 ;
        RECT 0.610 163.810 147.025 164.630 ;
        RECT 0.335 162.950 147.025 163.810 ;
        RECT 0.610 162.130 146.750 162.950 ;
        RECT 0.335 161.270 147.025 162.130 ;
        RECT 0.610 160.450 147.025 161.270 ;
        RECT 0.335 160.430 147.025 160.450 ;
        RECT 0.335 159.610 146.750 160.430 ;
        RECT 0.335 159.590 147.025 159.610 ;
        RECT 0.610 158.770 147.025 159.590 ;
        RECT 0.335 157.910 147.025 158.770 ;
        RECT 0.610 157.090 146.750 157.910 ;
        RECT 0.335 156.230 147.025 157.090 ;
        RECT 0.610 155.410 147.025 156.230 ;
        RECT 0.335 155.390 147.025 155.410 ;
        RECT 0.335 154.570 146.750 155.390 ;
        RECT 0.335 154.550 147.025 154.570 ;
        RECT 0.610 153.730 147.025 154.550 ;
        RECT 0.335 152.870 147.025 153.730 ;
        RECT 0.610 152.050 146.750 152.870 ;
        RECT 0.335 151.190 147.025 152.050 ;
        RECT 0.610 150.370 147.025 151.190 ;
        RECT 0.335 149.510 147.025 150.370 ;
        RECT 0.610 148.690 146.750 149.510 ;
        RECT 0.335 147.830 147.025 148.690 ;
        RECT 0.610 147.010 147.025 147.830 ;
        RECT 0.335 146.990 147.025 147.010 ;
        RECT 0.335 146.170 146.750 146.990 ;
        RECT 0.335 146.150 147.025 146.170 ;
        RECT 0.610 145.330 147.025 146.150 ;
        RECT 0.335 144.470 147.025 145.330 ;
        RECT 0.610 143.650 146.750 144.470 ;
        RECT 0.335 142.790 147.025 143.650 ;
        RECT 0.610 141.970 147.025 142.790 ;
        RECT 0.335 141.950 147.025 141.970 ;
        RECT 0.335 141.130 146.750 141.950 ;
        RECT 0.335 141.110 147.025 141.130 ;
        RECT 0.610 140.290 147.025 141.110 ;
        RECT 0.335 139.430 147.025 140.290 ;
        RECT 0.610 138.610 146.750 139.430 ;
        RECT 0.335 137.750 147.025 138.610 ;
        RECT 0.610 136.930 147.025 137.750 ;
        RECT 0.335 136.910 147.025 136.930 ;
        RECT 0.335 136.090 146.750 136.910 ;
        RECT 0.335 136.070 147.025 136.090 ;
        RECT 0.610 135.250 147.025 136.070 ;
        RECT 0.335 134.390 147.025 135.250 ;
        RECT 0.610 133.570 146.750 134.390 ;
        RECT 0.335 132.710 147.025 133.570 ;
        RECT 0.610 131.890 147.025 132.710 ;
        RECT 0.335 131.870 147.025 131.890 ;
        RECT 0.335 131.050 146.750 131.870 ;
        RECT 0.335 131.030 147.025 131.050 ;
        RECT 0.610 130.210 147.025 131.030 ;
        RECT 0.335 129.350 147.025 130.210 ;
        RECT 0.610 128.530 147.025 129.350 ;
        RECT 0.335 128.510 147.025 128.530 ;
        RECT 0.335 127.690 146.750 128.510 ;
        RECT 0.335 127.670 147.025 127.690 ;
        RECT 0.610 126.850 147.025 127.670 ;
        RECT 0.335 125.990 147.025 126.850 ;
        RECT 0.610 125.170 146.750 125.990 ;
        RECT 0.335 124.310 147.025 125.170 ;
        RECT 0.610 123.490 147.025 124.310 ;
        RECT 0.335 123.470 147.025 123.490 ;
        RECT 0.335 122.650 146.750 123.470 ;
        RECT 0.335 122.630 147.025 122.650 ;
        RECT 0.610 121.810 147.025 122.630 ;
        RECT 0.335 120.950 147.025 121.810 ;
        RECT 0.610 120.130 146.750 120.950 ;
        RECT 0.335 119.270 147.025 120.130 ;
        RECT 0.610 118.450 147.025 119.270 ;
        RECT 0.335 118.430 147.025 118.450 ;
        RECT 0.335 117.610 146.750 118.430 ;
        RECT 0.335 117.590 147.025 117.610 ;
        RECT 0.610 116.770 147.025 117.590 ;
        RECT 0.335 115.910 147.025 116.770 ;
        RECT 0.610 115.090 146.750 115.910 ;
        RECT 0.335 114.230 147.025 115.090 ;
        RECT 0.610 113.410 147.025 114.230 ;
        RECT 0.335 113.390 147.025 113.410 ;
        RECT 0.335 112.570 146.750 113.390 ;
        RECT 0.335 112.550 147.025 112.570 ;
        RECT 0.610 111.730 147.025 112.550 ;
        RECT 0.335 110.870 147.025 111.730 ;
        RECT 0.610 110.050 146.750 110.870 ;
        RECT 0.335 109.190 147.025 110.050 ;
        RECT 0.610 108.370 147.025 109.190 ;
        RECT 0.335 107.510 147.025 108.370 ;
        RECT 0.610 106.690 146.750 107.510 ;
        RECT 0.335 105.830 147.025 106.690 ;
        RECT 0.610 105.010 147.025 105.830 ;
        RECT 0.335 104.990 147.025 105.010 ;
        RECT 0.335 104.170 146.750 104.990 ;
        RECT 0.335 104.150 147.025 104.170 ;
        RECT 0.610 103.330 147.025 104.150 ;
        RECT 0.335 102.470 147.025 103.330 ;
        RECT 0.610 101.650 146.750 102.470 ;
        RECT 0.335 100.790 147.025 101.650 ;
        RECT 0.610 99.970 147.025 100.790 ;
        RECT 0.335 99.950 147.025 99.970 ;
        RECT 0.335 99.130 146.750 99.950 ;
        RECT 0.335 99.110 147.025 99.130 ;
        RECT 0.610 98.290 147.025 99.110 ;
        RECT 0.335 97.430 147.025 98.290 ;
        RECT 0.610 96.610 146.750 97.430 ;
        RECT 0.335 95.750 147.025 96.610 ;
        RECT 0.610 94.930 147.025 95.750 ;
        RECT 0.335 94.910 147.025 94.930 ;
        RECT 0.335 94.090 146.750 94.910 ;
        RECT 0.335 94.070 147.025 94.090 ;
        RECT 0.610 93.250 147.025 94.070 ;
        RECT 0.335 92.390 147.025 93.250 ;
        RECT 0.610 91.570 146.750 92.390 ;
        RECT 0.335 90.710 147.025 91.570 ;
        RECT 0.610 89.890 147.025 90.710 ;
        RECT 0.335 89.870 147.025 89.890 ;
        RECT 0.335 89.050 146.750 89.870 ;
        RECT 0.335 89.030 147.025 89.050 ;
        RECT 0.610 88.210 147.025 89.030 ;
        RECT 0.335 87.350 147.025 88.210 ;
        RECT 0.610 86.530 147.025 87.350 ;
        RECT 0.335 85.670 147.025 86.530 ;
        RECT 0.610 84.850 147.025 85.670 ;
        RECT 0.335 84.830 147.025 84.850 ;
        RECT 0.335 84.010 146.750 84.830 ;
        RECT 0.335 83.990 147.025 84.010 ;
        RECT 0.610 83.170 147.025 83.990 ;
        RECT 0.335 82.310 147.025 83.170 ;
        RECT 0.610 81.490 146.750 82.310 ;
        RECT 0.335 80.630 147.025 81.490 ;
        RECT 0.610 79.810 147.025 80.630 ;
        RECT 0.335 79.790 147.025 79.810 ;
        RECT 0.335 78.970 146.750 79.790 ;
        RECT 0.335 78.950 147.025 78.970 ;
        RECT 0.610 78.130 147.025 78.950 ;
        RECT 0.335 77.270 147.025 78.130 ;
        RECT 0.610 76.450 146.750 77.270 ;
        RECT 0.335 75.590 147.025 76.450 ;
        RECT 0.610 74.770 147.025 75.590 ;
        RECT 0.335 74.750 147.025 74.770 ;
        RECT 0.335 73.930 146.750 74.750 ;
        RECT 0.335 73.910 147.025 73.930 ;
        RECT 0.610 73.090 147.025 73.910 ;
        RECT 0.335 72.230 147.025 73.090 ;
        RECT 0.610 71.410 146.750 72.230 ;
        RECT 0.335 70.550 147.025 71.410 ;
        RECT 0.610 69.730 147.025 70.550 ;
        RECT 0.335 69.710 147.025 69.730 ;
        RECT 0.335 68.890 146.750 69.710 ;
        RECT 0.335 68.870 147.025 68.890 ;
        RECT 0.610 68.050 147.025 68.870 ;
        RECT 0.335 67.190 147.025 68.050 ;
        RECT 0.610 66.370 146.750 67.190 ;
        RECT 0.335 65.510 147.025 66.370 ;
        RECT 0.610 64.690 147.025 65.510 ;
        RECT 0.335 64.670 147.025 64.690 ;
        RECT 0.335 63.850 146.750 64.670 ;
        RECT 0.335 63.830 147.025 63.850 ;
        RECT 0.610 63.010 147.025 63.830 ;
        RECT 0.335 62.150 147.025 63.010 ;
        RECT 0.610 61.330 146.750 62.150 ;
        RECT 0.335 60.470 147.025 61.330 ;
        RECT 0.610 59.650 147.025 60.470 ;
        RECT 0.335 59.630 147.025 59.650 ;
        RECT 0.335 58.810 146.750 59.630 ;
        RECT 0.335 57.110 147.025 58.810 ;
        RECT 0.335 56.290 146.750 57.110 ;
        RECT 0.335 54.590 147.025 56.290 ;
        RECT 0.335 53.770 146.750 54.590 ;
        RECT 0.335 52.910 147.025 53.770 ;
        RECT 0.610 52.090 147.025 52.910 ;
        RECT 0.335 52.070 147.025 52.090 ;
        RECT 0.610 51.250 146.750 52.070 ;
        RECT 0.335 51.230 147.025 51.250 ;
        RECT 0.610 50.410 147.025 51.230 ;
        RECT 0.335 50.390 147.025 50.410 ;
        RECT 0.610 49.570 147.025 50.390 ;
        RECT 0.335 49.550 147.025 49.570 ;
        RECT 0.610 48.730 146.750 49.550 ;
        RECT 0.335 48.710 147.025 48.730 ;
        RECT 0.610 47.890 147.025 48.710 ;
        RECT 0.335 47.870 147.025 47.890 ;
        RECT 0.610 47.050 147.025 47.870 ;
        RECT 0.335 47.030 147.025 47.050 ;
        RECT 0.610 46.210 146.750 47.030 ;
        RECT 0.335 46.190 147.025 46.210 ;
        RECT 0.610 45.370 147.025 46.190 ;
        RECT 0.335 45.350 147.025 45.370 ;
        RECT 0.610 44.530 147.025 45.350 ;
        RECT 0.335 44.510 147.025 44.530 ;
        RECT 0.610 43.690 146.750 44.510 ;
        RECT 0.335 43.670 147.025 43.690 ;
        RECT 0.610 42.850 147.025 43.670 ;
        RECT 0.335 42.830 147.025 42.850 ;
        RECT 0.610 42.010 147.025 42.830 ;
        RECT 0.335 41.990 147.025 42.010 ;
        RECT 0.610 41.170 146.750 41.990 ;
        RECT 0.335 41.150 147.025 41.170 ;
        RECT 0.610 40.330 147.025 41.150 ;
        RECT 0.335 40.310 147.025 40.330 ;
        RECT 0.610 39.490 147.025 40.310 ;
        RECT 0.335 39.470 147.025 39.490 ;
        RECT 0.335 38.650 146.750 39.470 ;
        RECT 0.335 36.950 147.025 38.650 ;
        RECT 0.335 36.130 146.750 36.950 ;
        RECT 0.335 34.430 147.025 36.130 ;
        RECT 0.335 33.610 146.750 34.430 ;
        RECT 0.335 32.750 147.025 33.610 ;
        RECT 0.610 31.930 147.025 32.750 ;
        RECT 0.335 31.910 147.025 31.930 ;
        RECT 0.335 31.090 146.750 31.910 ;
        RECT 0.335 31.070 147.025 31.090 ;
        RECT 0.610 30.250 147.025 31.070 ;
        RECT 0.335 29.390 147.025 30.250 ;
        RECT 0.610 28.570 146.750 29.390 ;
        RECT 0.335 27.710 147.025 28.570 ;
        RECT 0.610 26.890 147.025 27.710 ;
        RECT 0.335 26.870 147.025 26.890 ;
        RECT 0.335 26.050 146.750 26.870 ;
        RECT 0.335 26.030 147.025 26.050 ;
        RECT 0.610 25.210 147.025 26.030 ;
        RECT 0.335 24.350 147.025 25.210 ;
        RECT 0.610 23.530 146.750 24.350 ;
        RECT 0.335 22.670 147.025 23.530 ;
        RECT 0.610 21.850 147.025 22.670 ;
        RECT 0.335 21.830 147.025 21.850 ;
        RECT 0.335 21.010 146.750 21.830 ;
        RECT 0.335 20.990 147.025 21.010 ;
        RECT 0.610 20.170 147.025 20.990 ;
        RECT 0.335 19.310 147.025 20.170 ;
        RECT 0.335 18.490 146.750 19.310 ;
        RECT 0.335 16.790 147.025 18.490 ;
        RECT 0.610 15.970 146.750 16.790 ;
        RECT 0.335 15.950 147.025 15.970 ;
        RECT 0.610 15.130 147.025 15.950 ;
        RECT 0.335 15.110 147.025 15.130 ;
        RECT 0.610 14.290 147.025 15.110 ;
        RECT 0.335 14.270 147.025 14.290 ;
        RECT 0.610 13.450 146.750 14.270 ;
        RECT 0.335 13.430 147.025 13.450 ;
        RECT 0.610 12.610 147.025 13.430 ;
        RECT 0.335 12.590 147.025 12.610 ;
        RECT 0.610 11.770 147.025 12.590 ;
        RECT 0.335 11.750 147.025 11.770 ;
        RECT 0.610 10.930 146.750 11.750 ;
        RECT 0.335 10.910 147.025 10.930 ;
        RECT 0.610 10.090 147.025 10.910 ;
        RECT 0.335 9.230 147.025 10.090 ;
        RECT 0.335 8.410 146.750 9.230 ;
        RECT 0.335 6.710 147.025 8.410 ;
        RECT 0.610 5.890 146.750 6.710 ;
        RECT 0.335 5.030 147.025 5.890 ;
        RECT 0.610 4.210 147.025 5.030 ;
        RECT 0.335 3.350 147.025 4.210 ;
        RECT 0.610 2.530 147.025 3.350 ;
        RECT 0.335 2.510 147.025 2.530 ;
        RECT 0.335 1.690 146.750 2.510 ;
        RECT 0.335 1.670 147.025 1.690 ;
        RECT 0.610 0.850 147.025 1.670 ;
        RECT 0.335 0.315 147.025 0.850 ;
      LAYER Metal4 ;
        RECT 0.860 0.275 15.170 215.185 ;
        RECT 17.790 0.275 21.370 215.185 ;
        RECT 23.990 0.275 90.770 215.185 ;
        RECT 93.390 0.275 96.970 215.185 ;
        RECT 99.590 0.275 146.980 215.185 ;
      LAYER TopMetal1 ;
        RECT 3.980 5.380 128.020 198.540 ;
  END
END RAM_IO
END LIBRARY

